###############################################################
#  Generated by:      Cadence Innovus 21.14-s109_1
#  OS:                Linux x86_64(Host ID caen-vnc-mi15.engin.umich.edu)
#  Generated on:      Sun Mar 26 22:47:20 2023
#  Design:            decoder
#  Command:           write_lef_abstract /afs/umich.edu/class/eecs627/w23/students/yihengfu/HW/apr/data/decoder.lef -specifyTopLayer 4 -stripePin -PGpinLayers 4
###############################################################

VERSION 5.8 ;

BUSBITCHARS "[]" ;
DIVIDERCHAR "/" ;

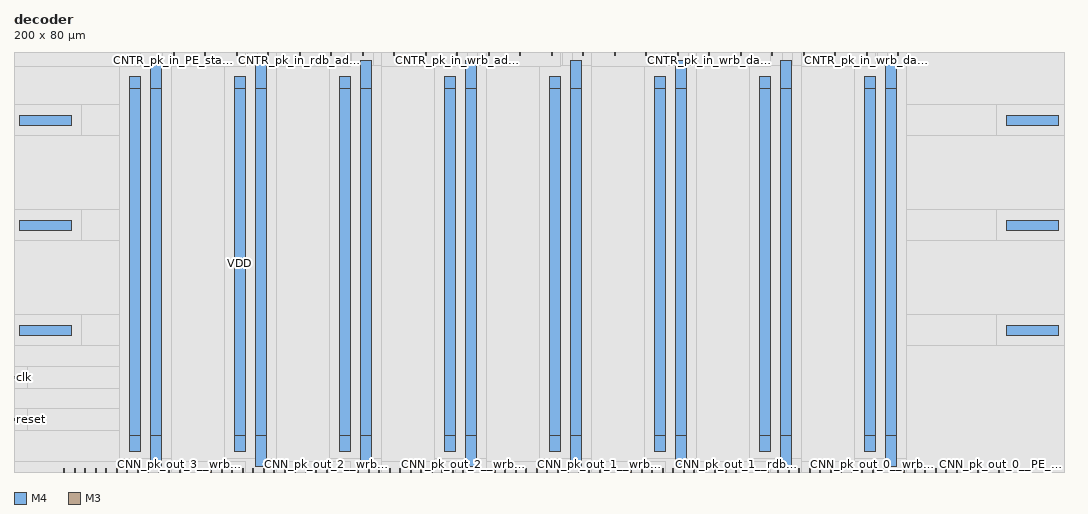
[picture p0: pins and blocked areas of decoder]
MACRO decoder
  CLASS BLOCK ;
  SIZE 200.000000 BY 80.000000 ;
  FOREIGN decoder 0.000000 0.000000 ;
  ORIGIN 0 0 ;
  SYMMETRY X Y R90 ;
  PIN clk
    DIRECTION INPUT ;
    USE SIGNAL ;
    ANTENNAPARTIALMETALAREA 7.72 LAYER M4  ;
    ANTENNAPARTIALMETALSIDEAREA 0.0776 LAYER M4  ;
    ANTENNAMODEL OXIDE1 ;
    ANTENNAGATEAREA 0.2136 LAYER M4  ;
    ANTENNAMAXAREACAR 37.7463 LAYER M4  ;
    ANTENNAMAXSIDEAREACAR 0.384363 LAYER M4  ;
    ANTENNAMAXCUTCAR 0.93633 LAYER V4  ;
    PORT
      LAYER M4 ;
        RECT 0.000000 17.900000 0.600000 18.100000 ;
    END
  END clk
  PIN reset
    DIRECTION INPUT ;
    USE SIGNAL ;
    ANTENNAPARTIALMETALAREA 0.18 LAYER M4  ;
    ANTENNAPARTIALMETALSIDEAREA 0.0022 LAYER M4  ;
    ANTENNAMODEL OXIDE1 ;
    ANTENNAGATEAREA 0.0888 LAYER M4  ;
    ANTENNAMAXAREACAR 64.3829 LAYER M4  ;
    ANTENNAMAXSIDEAREACAR 0.66509 LAYER M4  ;
    ANTENNAMAXCUTCAR 2.25225 LAYER V4  ;
    PORT
      LAYER M4 ;
        RECT 0.000000 9.900000 0.600000 10.100000 ;
    END
  END reset
  PIN CNTR_pk_in_PE_state__2_
    DIRECTION INPUT ;
    USE SIGNAL ;
    ANTENNAPARTIALMETALAREA 0.88 LAYER M3  ;
    ANTENNAPARTIALMETALSIDEAREA 0.0088 LAYER M3  ;
    ANTENNAPARTIALCUTAREA 0.08 LAYER V3  ;
    ANTENNAPARTIALMETALAREA 5.48 LAYER M4  ;
    ANTENNAPARTIALMETALSIDEAREA 0.0552 LAYER M4  ;
    ANTENNAMODEL OXIDE1 ;
    ANTENNAGATEAREA 0.0888 LAYER M4  ;
    ANTENNAMAXAREACAR 95.6892 LAYER M4  ;
    ANTENNAMAXSIDEAREACAR 0.973649 LAYER M4  ;
    ANTENNAMAXCUTCAR 2.25225 LAYER V4  ;
    PORT
      LAYER M3 ;
        RECT 42.300000 79.400000 42.500000 80.000000 ;
    END
  END CNTR_pk_in_PE_state__2_
  PIN CNTR_pk_in_PE_state__1_
    DIRECTION INPUT ;
    USE SIGNAL ;
    ANTENNAPARTIALMETALAREA 0.32 LAYER M3  ;
    ANTENNAPARTIALMETALSIDEAREA 0.0032 LAYER M3  ;
    ANTENNAPARTIALCUTAREA 0.08 LAYER V3  ;
    ANTENNAPARTIALMETALAREA 1.48 LAYER M4  ;
    ANTENNAPARTIALMETALSIDEAREA 0.0152 LAYER M4  ;
    ANTENNAMODEL OXIDE1 ;
    ANTENNAGATEAREA 0.0888 LAYER M4  ;
    ANTENNAMAXAREACAR 68.2117 LAYER M4  ;
    ANTENNAMAXSIDEAREACAR 0.703378 LAYER M4  ;
    ANTENNAMAXCUTCAR 2.25225 LAYER V4  ;
    PORT
      LAYER M3 ;
        RECT 36.300000 79.400000 36.500000 80.000000 ;
    END
  END CNTR_pk_in_PE_state__1_
  PIN CNTR_pk_in_PE_state__0_
    DIRECTION INPUT ;
    USE SIGNAL ;
    ANTENNAPARTIALMETALAREA 0.32 LAYER M3  ;
    ANTENNAPARTIALMETALSIDEAREA 0.0032 LAYER M3  ;
    ANTENNAPARTIALCUTAREA 0.08 LAYER V3  ;
    ANTENNAPARTIALMETALAREA 3.88 LAYER M4  ;
    ANTENNAPARTIALMETALSIDEAREA 0.0392 LAYER M4  ;
    ANTENNAMODEL OXIDE1 ;
    ANTENNAGATEAREA 0.0888 LAYER M4  ;
    ANTENNAMAXAREACAR 63.7072 LAYER M4  ;
    ANTENNAMAXSIDEAREACAR 0.658333 LAYER M4  ;
    ANTENNAMAXCUTCAR 2.25225 LAYER V4  ;
    PORT
      LAYER M3 ;
        RECT 30.300000 79.400000 30.500000 80.000000 ;
    END
  END CNTR_pk_in_PE_state__0_
  PIN CNTR_pk_in_wrb_data__7_
    DIRECTION INPUT ;
    USE SIGNAL ;
    ANTENNAPARTIALMETALAREA 0.16 LAYER M3  ;
    ANTENNAPARTIALMETALSIDEAREA 0.0016 LAYER M3  ;
    ANTENNAPARTIALCUTAREA 0.08 LAYER V3  ;
    ANTENNAPARTIALMETALAREA 4.04 LAYER M4  ;
    ANTENNAPARTIALMETALSIDEAREA 0.0408 LAYER M4  ;
    ANTENNAMODEL OXIDE1 ;
    ANTENNAGATEAREA 0.0888 LAYER M4  ;
    ANTENNAMAXAREACAR 57.8514 LAYER M4  ;
    ANTENNAMAXSIDEAREACAR 0.59527 LAYER M4  ;
    ANTENNAMAXCUTCAR 2.25225 LAYER V4  ;
    PORT
      LAYER M3 ;
        RECT 168.300000 79.400000 168.500000 80.000000 ;
    END
  END CNTR_pk_in_wrb_data__7_
  PIN CNTR_pk_in_wrb_data__6_
    DIRECTION INPUT ;
    USE SIGNAL ;
    ANTENNAPARTIALMETALAREA 1.12 LAYER M3  ;
    ANTENNAPARTIALMETALSIDEAREA 0.0112 LAYER M3  ;
    ANTENNAPARTIALCUTAREA 0.08 LAYER V3  ;
    ANTENNAPARTIALMETALAREA 1.48 LAYER M4  ;
    ANTENNAPARTIALMETALSIDEAREA 0.0152 LAYER M4  ;
    ANTENNAMODEL OXIDE1 ;
    ANTENNAGATEAREA 0.0888 LAYER M4  ;
    ANTENNAMAXAREACAR 49.7432 LAYER M4  ;
    ANTENNAMAXSIDEAREACAR 0.514189 LAYER M4  ;
    ANTENNAMAXCUTCAR 2.25225 LAYER V4  ;
    PORT
      LAYER M3 ;
        RECT 162.300000 79.400000 162.500000 80.000000 ;
    END
  END CNTR_pk_in_wrb_data__6_
  PIN CNTR_pk_in_wrb_data__5_
    DIRECTION INPUT ;
    USE SIGNAL ;
    ANTENNAPARTIALMETALAREA 1.2 LAYER M3  ;
    ANTENNAPARTIALMETALSIDEAREA 0.012 LAYER M3  ;
    ANTENNAPARTIALCUTAREA 0.08 LAYER V3  ;
    ANTENNAPARTIALMETALAREA 3.96 LAYER M4  ;
    ANTENNAPARTIALMETALSIDEAREA 0.04 LAYER M4  ;
    ANTENNAMODEL OXIDE1 ;
    ANTENNAGATEAREA 0.0888 LAYER M4  ;
    ANTENNAMAXAREACAR 61.455 LAYER M4  ;
    ANTENNAMAXSIDEAREACAR 0.631306 LAYER M4  ;
    ANTENNAMAXCUTCAR 2.25225 LAYER V4  ;
    PORT
      LAYER M3 ;
        RECT 156.300000 79.400000 156.500000 80.000000 ;
    END
  END CNTR_pk_in_wrb_data__5_
  PIN CNTR_pk_in_wrb_data__4_
    DIRECTION INPUT ;
    USE SIGNAL ;
    ANTENNAPARTIALMETALAREA 0.4 LAYER M3  ;
    ANTENNAPARTIALMETALSIDEAREA 0.004 LAYER M3  ;
    ANTENNAPARTIALCUTAREA 0.08 LAYER V3  ;
    ANTENNAPARTIALMETALAREA 1.56 LAYER M4  ;
    ANTENNAPARTIALMETALSIDEAREA 0.016 LAYER M4  ;
    ANTENNAMODEL OXIDE1 ;
    ANTENNAGATEAREA 0.0888 LAYER M4  ;
    ANTENNAMAXAREACAR 33.527 LAYER M4  ;
    ANTENNAMAXSIDEAREACAR 0.352027 LAYER M4  ;
    ANTENNAMAXCUTCAR 2.25225 LAYER V4  ;
    PORT
      LAYER M3 ;
        RECT 150.300000 79.400000 150.500000 80.000000 ;
    END
  END CNTR_pk_in_wrb_data__4_
  PIN CNTR_pk_in_wrb_data__3_
    DIRECTION INPUT ;
    USE SIGNAL ;
    ANTENNAPARTIALMETALAREA 0.24 LAYER M3  ;
    ANTENNAPARTIALMETALSIDEAREA 0.0024 LAYER M3  ;
    ANTENNAPARTIALCUTAREA 0.08 LAYER V3  ;
    ANTENNAPARTIALMETALAREA 1.64 LAYER M4  ;
    ANTENNAPARTIALMETALSIDEAREA 0.0168 LAYER M4  ;
    ANTENNAMODEL OXIDE1 ;
    ANTENNAGATEAREA 0.0888 LAYER M4  ;
    ANTENNAMAXAREACAR 27.2207 LAYER M4  ;
    ANTENNAMAXSIDEAREACAR 0.288964 LAYER M4  ;
    ANTENNAMAXCUTCAR 2.25225 LAYER V4  ;
    PORT
      LAYER M3 ;
        RECT 144.300000 79.400000 144.500000 80.000000 ;
    END
  END CNTR_pk_in_wrb_data__3_
  PIN CNTR_pk_in_wrb_data__2_
    DIRECTION INPUT ;
    USE SIGNAL ;
    ANTENNAPARTIALMETALAREA 1.2 LAYER M3  ;
    ANTENNAPARTIALMETALSIDEAREA 0.012 LAYER M3  ;
    ANTENNAPARTIALCUTAREA 0.08 LAYER V3  ;
    ANTENNAPARTIALMETALAREA 1.48 LAYER M4  ;
    ANTENNAPARTIALMETALSIDEAREA 0.0152 LAYER M4  ;
    ANTENNAMODEL OXIDE1 ;
    ANTENNAGATEAREA 0.0888 LAYER M4  ;
    ANTENNAMAXAREACAR 37.5811 LAYER M4  ;
    ANTENNAMAXSIDEAREACAR 0.397072 LAYER M4  ;
    ANTENNAMAXCUTCAR 2.25225 LAYER V4  ;
    PORT
      LAYER M3 ;
        RECT 138.300000 79.400000 138.500000 80.000000 ;
    END
  END CNTR_pk_in_wrb_data__2_
  PIN CNTR_pk_in_wrb_data__1_
    DIRECTION INPUT ;
    USE SIGNAL ;
    ANTENNAPARTIALMETALAREA 0.32 LAYER M3  ;
    ANTENNAPARTIALMETALSIDEAREA 0.0032 LAYER M3  ;
    ANTENNAPARTIALCUTAREA 0.08 LAYER V3  ;
    ANTENNAPARTIALMETALAREA 6.92 LAYER M4  ;
    ANTENNAPARTIALMETALSIDEAREA 0.0696 LAYER M4  ;
    ANTENNAMODEL OXIDE1 ;
    ANTENNAGATEAREA 0.0888 LAYER M4  ;
    ANTENNAMAXAREACAR 87.5811 LAYER M4  ;
    ANTENNAMAXSIDEAREACAR 0.892568 LAYER M4  ;
    ANTENNAMAXCUTCAR 2.25225 LAYER V4  ;
    PORT
      LAYER M3 ;
        RECT 132.300000 79.400000 132.500000 80.000000 ;
    END
  END CNTR_pk_in_wrb_data__1_
  PIN CNTR_pk_in_wrb_data__0_
    DIRECTION INPUT ;
    USE SIGNAL ;
    ANTENNAPARTIALMETALAREA 1.12 LAYER M3  ;
    ANTENNAPARTIALMETALSIDEAREA 0.0112 LAYER M3  ;
    ANTENNAPARTIALCUTAREA 0.08 LAYER V3  ;
    ANTENNAPARTIALMETALAREA 1.48 LAYER M4  ;
    ANTENNAPARTIALMETALSIDEAREA 0.0152 LAYER M4  ;
    ANTENNAMODEL OXIDE1 ;
    ANTENNAGATEAREA 0.0888 LAYER M4  ;
    ANTENNAMAXAREACAR 31.2748 LAYER M4  ;
    ANTENNAMAXSIDEAREACAR 0.334009 LAYER M4  ;
    ANTENNAMAXCUTCAR 2.25225 LAYER V4  ;
    PORT
      LAYER M3 ;
        RECT 126.300000 79.400000 126.500000 80.000000 ;
    END
  END CNTR_pk_in_wrb_data__0_
  PIN CNTR_pk_in_wrb_addr__7_
    DIRECTION INPUT ;
    USE SIGNAL ;
    ANTENNAPARTIALMETALAREA 0.4 LAYER M3  ;
    ANTENNAPARTIALMETALSIDEAREA 0.004 LAYER M3  ;
    ANTENNAPARTIALCUTAREA 0.08 LAYER V3  ;
    ANTENNAPARTIALMETALAREA 1.64 LAYER M4  ;
    ANTENNAPARTIALMETALSIDEAREA 0.0168 LAYER M4  ;
    ANTENNAMODEL OXIDE1 ;
    ANTENNAGATEAREA 0.0888 LAYER M4  ;
    ANTENNAMAXAREACAR 43.4369 LAYER M4  ;
    ANTENNAMAXSIDEAREACAR 0.451126 LAYER M4  ;
    ANTENNAMAXCUTCAR 2.25225 LAYER V4  ;
    PORT
      LAYER M3 ;
        RECT 120.300000 79.400000 120.500000 80.000000 ;
    END
  END CNTR_pk_in_wrb_addr__7_
  PIN CNTR_pk_in_wrb_addr__6_
    DIRECTION INPUT ;
    USE SIGNAL ;
    ANTENNAPARTIALMETALAREA 0.96 LAYER M3  ;
    ANTENNAPARTIALMETALSIDEAREA 0.0096 LAYER M3  ;
    ANTENNAPARTIALCUTAREA 0.08 LAYER V3  ;
    ANTENNAPARTIALMETALAREA 2.28 LAYER M4  ;
    ANTENNAPARTIALMETALSIDEAREA 0.0232 LAYER M4  ;
    ANTENNAMODEL OXIDE1 ;
    ANTENNAGATEAREA 0.0888 LAYER M4  ;
    ANTENNAMAXAREACAR 38.482 LAYER M4  ;
    ANTENNAMAXSIDEAREACAR 0.406081 LAYER M4  ;
    ANTENNAMAXCUTCAR 2.25225 LAYER V4  ;
    PORT
      LAYER M3 ;
        RECT 114.300000 79.400000 114.500000 80.000000 ;
    END
  END CNTR_pk_in_wrb_addr__6_
  PIN CNTR_pk_in_wrb_addr__5_
    DIRECTION INPUT ;
    USE SIGNAL ;
    ANTENNAPARTIALMETALAREA 0.16 LAYER M3  ;
    ANTENNAPARTIALMETALSIDEAREA 0.0016 LAYER M3  ;
    ANTENNAPARTIALCUTAREA 0.08 LAYER V3  ;
    ANTENNAPARTIALMETALAREA 7.96 LAYER M4  ;
    ANTENNAPARTIALMETALSIDEAREA 0.08 LAYER M4  ;
    ANTENNAMODEL OXIDE1 ;
    ANTENNAGATEAREA 0.0888 LAYER M4  ;
    ANTENNAMAXAREACAR 101.095 LAYER M4  ;
    ANTENNAMAXSIDEAREACAR 1.0277 LAYER M4  ;
    ANTENNAMAXCUTCAR 2.25225 LAYER V4  ;
    PORT
      LAYER M3 ;
        RECT 108.300000 79.400000 108.500000 80.000000 ;
    END
  END CNTR_pk_in_wrb_addr__5_
  PIN CNTR_pk_in_wrb_addr__4_
    DIRECTION INPUT ;
    USE SIGNAL ;
    ANTENNAPARTIALMETALAREA 0.8 LAYER M3  ;
    ANTENNAPARTIALMETALSIDEAREA 0.008 LAYER M3  ;
    ANTENNAPARTIALCUTAREA 0.08 LAYER V3  ;
    ANTENNAPARTIALMETALAREA 1.32 LAYER M4  ;
    ANTENNAPARTIALMETALSIDEAREA 0.0136 LAYER M4  ;
    ANTENNAMODEL OXIDE1 ;
    ANTENNAGATEAREA 0.0888 LAYER M4  ;
    ANTENNAMAXAREACAR 25.8694 LAYER M4  ;
    ANTENNAMAXSIDEAREACAR 0.279955 LAYER M4  ;
    ANTENNAMAXCUTCAR 2.25225 LAYER V4  ;
    PORT
      LAYER M3 ;
        RECT 102.300000 79.400000 102.500000 80.000000 ;
    END
  END CNTR_pk_in_wrb_addr__4_
  PIN CNTR_pk_in_wrb_addr__3_
    DIRECTION INPUT ;
    USE SIGNAL ;
    ANTENNAPARTIALMETALAREA 1.12 LAYER M3  ;
    ANTENNAPARTIALMETALSIDEAREA 0.0112 LAYER M3  ;
    ANTENNAPARTIALCUTAREA 0.08 LAYER V3  ;
    ANTENNAPARTIALMETALAREA 1.48 LAYER M4  ;
    ANTENNAPARTIALMETALSIDEAREA 0.0152 LAYER M4  ;
    ANTENNAMODEL OXIDE1 ;
    ANTENNAGATEAREA 0.0888 LAYER M4  ;
    ANTENNAMAXAREACAR 26.7703 LAYER M4  ;
    ANTENNAMAXSIDEAREACAR 0.288964 LAYER M4  ;
    ANTENNAMAXCUTCAR 2.25225 LAYER V4  ;
    PORT
      LAYER M3 ;
        RECT 96.300000 79.400000 96.500000 80.000000 ;
    END
  END CNTR_pk_in_wrb_addr__3_
  PIN CNTR_pk_in_wrb_addr__2_
    DIRECTION INPUT ;
    USE SIGNAL ;
    ANTENNAPARTIALMETALAREA 1.2 LAYER M3  ;
    ANTENNAPARTIALMETALSIDEAREA 0.012 LAYER M3  ;
    ANTENNAPARTIALCUTAREA 0.08 LAYER V3  ;
    ANTENNAPARTIALMETALAREA 4.68 LAYER M4  ;
    ANTENNAPARTIALMETALSIDEAREA 0.0472 LAYER M4  ;
    ANTENNAMODEL OXIDE1 ;
    ANTENNAGATEAREA 0.0888 LAYER M4  ;
    ANTENNAMAXAREACAR 65.509 LAYER M4  ;
    ANTENNAMAXSIDEAREACAR 0.676351 LAYER M4  ;
    ANTENNAMAXCUTCAR 2.25225 LAYER V4  ;
    PORT
      LAYER M3 ;
        RECT 90.300000 79.400000 90.500000 80.000000 ;
    END
  END CNTR_pk_in_wrb_addr__2_
  PIN CNTR_pk_in_wrb_addr__1_
    DIRECTION INPUT ;
    USE SIGNAL ;
    ANTENNAPARTIALMETALAREA 0.64 LAYER M3  ;
    ANTENNAPARTIALMETALSIDEAREA 0.0064 LAYER M3  ;
    ANTENNAPARTIALCUTAREA 0.08 LAYER V3  ;
    ANTENNAPARTIALMETALAREA 2.04 LAYER M4  ;
    ANTENNAPARTIALMETALSIDEAREA 0.0208 LAYER M4  ;
    ANTENNAMODEL OXIDE1 ;
    ANTENNAGATEAREA 0.0888 LAYER M4  ;
    ANTENNAMAXAREACAR 33.9775 LAYER M4  ;
    ANTENNAMAXSIDEAREACAR 0.361036 LAYER M4  ;
    ANTENNAMAXCUTCAR 2.25225 LAYER V4  ;
    PORT
      LAYER M3 ;
        RECT 84.300000 79.400000 84.500000 80.000000 ;
    END
  END CNTR_pk_in_wrb_addr__1_
  PIN CNTR_pk_in_wrb_addr__0_
    DIRECTION INPUT ;
    USE SIGNAL ;
    ANTENNAPARTIALMETALAREA 0.16 LAYER M3  ;
    ANTENNAPARTIALMETALSIDEAREA 0.0016 LAYER M3  ;
    ANTENNAPARTIALCUTAREA 0.08 LAYER V3  ;
    ANTENNAPARTIALMETALAREA 1.56 LAYER M4  ;
    ANTENNAPARTIALMETALSIDEAREA 0.016 LAYER M4  ;
    ANTENNAMODEL OXIDE1 ;
    ANTENNAGATEAREA 0.0888 LAYER M4  ;
    ANTENNAMAXAREACAR 38.482 LAYER M4  ;
    ANTENNAMAXSIDEAREACAR 0.406081 LAYER M4  ;
    ANTENNAMAXCUTCAR 2.25225 LAYER V4  ;
    PORT
      LAYER M3 ;
        RECT 78.300000 79.400000 78.500000 80.000000 ;
    END
  END CNTR_pk_in_wrb_addr__0_
  PIN CNTR_pk_in_wrb_
    DIRECTION INPUT ;
    USE SIGNAL ;
    ANTENNAPARTIALMETALAREA 1.2 LAYER M3  ;
    ANTENNAPARTIALMETALSIDEAREA 0.012 LAYER M3  ;
    ANTENNAPARTIALCUTAREA 0.08 LAYER V3  ;
    ANTENNAPARTIALMETALAREA 1.64 LAYER M4  ;
    ANTENNAPARTIALMETALSIDEAREA 0.0168 LAYER M4  ;
    ANTENNAMODEL OXIDE1 ;
    ANTENNAGATEAREA 0.0888 LAYER M4  ;
    ANTENNAMAXAREACAR 27.6712 LAYER M4  ;
    ANTENNAMAXSIDEAREACAR 0.297973 LAYER M4  ;
    ANTENNAMAXCUTCAR 2.25225 LAYER V4  ;
    PORT
      LAYER M3 ;
        RECT 72.300000 79.400000 72.500000 80.000000 ;
    END
  END CNTR_pk_in_wrb_
  PIN CNTR_pk_in_rdb_addr__3_
    DIRECTION INPUT ;
    USE SIGNAL ;
    ANTENNAPARTIALMETALAREA 0.48 LAYER M3  ;
    ANTENNAPARTIALMETALSIDEAREA 0.0048 LAYER M3  ;
    ANTENNAPARTIALCUTAREA 0.08 LAYER V3  ;
    ANTENNAPARTIALMETALAREA 6.28 LAYER M4  ;
    ANTENNAPARTIALMETALSIDEAREA 0.0632 LAYER M4  ;
    ANTENNAMODEL OXIDE1 ;
    ANTENNAGATEAREA 0.0888 LAYER M4  ;
    ANTENNAMAXAREACAR 80.3739 LAYER M4  ;
    ANTENNAMAXSIDEAREACAR 0.820495 LAYER M4  ;
    ANTENNAMAXCUTCAR 2.25225 LAYER V4  ;
    PORT
      LAYER M3 ;
        RECT 66.300000 79.400000 66.500000 80.000000 ;
    END
  END CNTR_pk_in_rdb_addr__3_
  PIN CNTR_pk_in_rdb_addr__2_
    DIRECTION INPUT ;
    USE SIGNAL ;
    ANTENNAPARTIALMETALAREA 0.72 LAYER M3  ;
    ANTENNAPARTIALMETALSIDEAREA 0.0072 LAYER M3  ;
    ANTENNAPARTIALCUTAREA 0.08 LAYER V3  ;
    ANTENNAPARTIALMETALAREA 1.48 LAYER M4  ;
    ANTENNAPARTIALMETALSIDEAREA 0.0152 LAYER M4  ;
    ANTENNAMODEL OXIDE1 ;
    ANTENNAGATEAREA 0.0888 LAYER M4  ;
    ANTENNAMAXAREACAR 26.7703 LAYER M4  ;
    ANTENNAMAXSIDEAREACAR 0.288964 LAYER M4  ;
    ANTENNAMAXCUTCAR 2.25225 LAYER V4  ;
    PORT
      LAYER M3 ;
        RECT 60.300000 79.400000 60.500000 80.000000 ;
    END
  END CNTR_pk_in_rdb_addr__2_
  PIN CNTR_pk_in_rdb_addr__1_
    DIRECTION INPUT ;
    USE SIGNAL ;
    ANTENNAPARTIALMETALAREA 1.12 LAYER M3  ;
    ANTENNAPARTIALMETALSIDEAREA 0.0112 LAYER M3  ;
    ANTENNAPARTIALCUTAREA 0.08 LAYER V3  ;
    ANTENNAPARTIALMETALAREA 5.4 LAYER M4  ;
    ANTENNAPARTIALMETALSIDEAREA 0.0544 LAYER M4  ;
    ANTENNAMODEL OXIDE1 ;
    ANTENNAGATEAREA 0.0888 LAYER M4  ;
    ANTENNAMAXAREACAR 82.1757 LAYER M4  ;
    ANTENNAMAXSIDEAREACAR 0.838513 LAYER M4  ;
    ANTENNAMAXCUTCAR 2.25225 LAYER V4  ;
    PORT
      LAYER M3 ;
        RECT 54.300000 79.400000 54.500000 80.000000 ;
    END
  END CNTR_pk_in_rdb_addr__1_
  PIN CNTR_pk_in_rdb_addr__0_
    DIRECTION INPUT ;
    USE SIGNAL ;
    ANTENNAPARTIALMETALAREA 0.14 LAYER M3  ;
    ANTENNAPARTIALMETALSIDEAREA 0.0014 LAYER M3  ;
    ANTENNAPARTIALCUTAREA 0.08 LAYER V3  ;
    ANTENNAPARTIALMETALAREA 1.4 LAYER M4  ;
    ANTENNAPARTIALMETALSIDEAREA 0.0144 LAYER M4  ;
    ANTENNAMODEL OXIDE1 ;
    ANTENNAGATEAREA 0.0888 LAYER M4  ;
    ANTENNAMAXAREACAR 44.3378 LAYER M4  ;
    ANTENNAMAXSIDEAREACAR 0.460135 LAYER M4  ;
    ANTENNAMAXCUTCAR 2.25225 LAYER V4  ;
    PORT
      LAYER M3 ;
        RECT 48.300000 79.400000 48.500000 80.000000 ;
    END
  END CNTR_pk_in_rdb_addr__0_
  PIN CNN_pk_out_3__PE_state__2_
    DIRECTION OUTPUT ;
    USE SIGNAL ;
    ANTENNAPARTIALMETALAREA 0.16 LAYER M3  ;
    ANTENNAPARTIALMETALSIDEAREA 0.0016 LAYER M3  ;
    ANTENNAPARTIALCUTAREA 0.08 LAYER V3  ;
    ANTENNADIFFAREA 3.52 LAYER M4  ;
    ANTENNAPARTIALMETALAREA 30.28 LAYER M4  ;
    ANTENNAPARTIALMETALSIDEAREA 0.3048 LAYER M4  ;
    PORT
      LAYER M3 ;
        RECT 49.500000 0.000000 49.700000 0.600000 ;
    END
  END CNN_pk_out_3__PE_state__2_
  PIN CNN_pk_out_3__PE_state__1_
    DIRECTION OUTPUT ;
    USE SIGNAL ;
    ANTENNAPARTIALMETALAREA 0.16 LAYER M3  ;
    ANTENNAPARTIALMETALSIDEAREA 0.0016 LAYER M3  ;
    ANTENNAPARTIALCUTAREA 0.08 LAYER V3  ;
    ANTENNADIFFAREA 3.52 LAYER M4  ;
    ANTENNAPARTIALMETALAREA 8.88 LAYER M4  ;
    ANTENNAPARTIALMETALSIDEAREA 0.0904 LAYER M4  ;
    PORT
      LAYER M3 ;
        RECT 51.500000 0.000000 51.700000 0.600000 ;
    END
  END CNN_pk_out_3__PE_state__1_
  PIN CNN_pk_out_3__PE_state__0_
    DIRECTION OUTPUT ;
    USE SIGNAL ;
    ANTENNAPARTIALMETALAREA 0.16 LAYER M3  ;
    ANTENNAPARTIALMETALSIDEAREA 0.0016 LAYER M3  ;
    ANTENNAPARTIALCUTAREA 0.08 LAYER V3  ;
    ANTENNADIFFAREA 3.52 LAYER M4  ;
    ANTENNAPARTIALMETALAREA 7.96 LAYER M4  ;
    ANTENNAPARTIALMETALSIDEAREA 0.0816 LAYER M4  ;
    PORT
      LAYER M3 ;
        RECT 53.500000 0.000000 53.700000 0.600000 ;
    END
  END CNN_pk_out_3__PE_state__0_
  PIN CNN_pk_out_3__wrb_data__7_
    DIRECTION OUTPUT ;
    USE SIGNAL ;
    ANTENNAPARTIALMETALAREA 0.16 LAYER M3  ;
    ANTENNAPARTIALMETALSIDEAREA 0.0016 LAYER M3  ;
    ANTENNAPARTIALCUTAREA 0.08 LAYER V3  ;
    ANTENNADIFFAREA 3.52 LAYER M4  ;
    ANTENNAPARTIALMETALAREA 8.24 LAYER M4  ;
    ANTENNAPARTIALMETALSIDEAREA 0.084 LAYER M4  ;
    PORT
      LAYER M3 ;
        RECT 9.500000 0.000000 9.700000 0.600000 ;
    END
  END CNN_pk_out_3__wrb_data__7_
  PIN CNN_pk_out_3__wrb_data__6_
    DIRECTION OUTPUT ;
    USE SIGNAL ;
    ANTENNAPARTIALMETALAREA 0.32 LAYER M3  ;
    ANTENNAPARTIALMETALSIDEAREA 0.0032 LAYER M3  ;
    ANTENNAPARTIALCUTAREA 0.08 LAYER V3  ;
    ANTENNADIFFAREA 3.52 LAYER M4  ;
    ANTENNAPARTIALMETALAREA 9.12 LAYER M4  ;
    ANTENNAPARTIALMETALSIDEAREA 0.0928 LAYER M4  ;
    PORT
      LAYER M3 ;
        RECT 11.500000 0.000000 11.700000 0.600000 ;
    END
  END CNN_pk_out_3__wrb_data__6_
  PIN CNN_pk_out_3__wrb_data__5_
    DIRECTION OUTPUT ;
    USE SIGNAL ;
    ANTENNAPARTIALMETALAREA 0.4 LAYER M3  ;
    ANTENNAPARTIALMETALSIDEAREA 0.004 LAYER M3  ;
    ANTENNAPARTIALCUTAREA 0.08 LAYER V3  ;
    ANTENNADIFFAREA 3.52 LAYER M4  ;
    ANTENNAPARTIALMETALAREA 26.16 LAYER M4  ;
    ANTENNAPARTIALMETALSIDEAREA 0.2632 LAYER M4  ;
    PORT
      LAYER M3 ;
        RECT 13.500000 0.000000 13.700000 0.600000 ;
    END
  END CNN_pk_out_3__wrb_data__5_
  PIN CNN_pk_out_3__wrb_data__4_
    DIRECTION OUTPUT ;
    USE SIGNAL ;
    ANTENNAPARTIALMETALAREA 0.4 LAYER M3  ;
    ANTENNAPARTIALMETALSIDEAREA 0.004 LAYER M3  ;
    ANTENNAPARTIALCUTAREA 0.08 LAYER V3  ;
    ANTENNADIFFAREA 3.52 LAYER M4  ;
    ANTENNAPARTIALMETALAREA 4.16 LAYER M4  ;
    ANTENNAPARTIALMETALSIDEAREA 0.0432 LAYER M4  ;
    PORT
      LAYER M3 ;
        RECT 15.500000 0.000000 15.700000 0.600000 ;
    END
  END CNN_pk_out_3__wrb_data__4_
  PIN CNN_pk_out_3__wrb_data__3_
    DIRECTION OUTPUT ;
    USE SIGNAL ;
    ANTENNAPARTIALMETALAREA 0.08 LAYER M3  ;
    ANTENNAPARTIALMETALSIDEAREA 0.0008 LAYER M3  ;
    ANTENNAPARTIALCUTAREA 0.04 LAYER V3  ;
    ANTENNADIFFAREA 3.52 LAYER M4  ;
    ANTENNAPARTIALMETALAREA 23.12 LAYER M4  ;
    ANTENNAPARTIALMETALSIDEAREA 0.2328 LAYER M4  ;
    PORT
      LAYER M3 ;
        RECT 17.500000 0.000000 17.700000 0.600000 ;
    END
  END CNN_pk_out_3__wrb_data__3_
  PIN CNN_pk_out_3__wrb_data__2_
    DIRECTION OUTPUT ;
    USE SIGNAL ;
    ANTENNAPARTIALMETALAREA 0.16 LAYER M3  ;
    ANTENNAPARTIALMETALSIDEAREA 0.0016 LAYER M3  ;
    ANTENNAPARTIALCUTAREA 0.08 LAYER V3  ;
    ANTENNADIFFAREA 3.52 LAYER M4  ;
    ANTENNAPARTIALMETALAREA 15.2 LAYER M4  ;
    ANTENNAPARTIALMETALSIDEAREA 0.1536 LAYER M4  ;
    PORT
      LAYER M3 ;
        RECT 19.500000 0.000000 19.700000 0.600000 ;
    END
  END CNN_pk_out_3__wrb_data__2_
  PIN CNN_pk_out_3__wrb_data__1_
    DIRECTION OUTPUT ;
    USE SIGNAL ;
    ANTENNAPARTIALMETALAREA 0.16 LAYER M3  ;
    ANTENNAPARTIALMETALSIDEAREA 0.0016 LAYER M3  ;
    ANTENNAPARTIALCUTAREA 0.08 LAYER V3  ;
    ANTENNADIFFAREA 3.52 LAYER M4  ;
    ANTENNAPARTIALMETALAREA 23.6 LAYER M4  ;
    ANTENNAPARTIALMETALSIDEAREA 0.2376 LAYER M4  ;
    PORT
      LAYER M3 ;
        RECT 21.500000 0.000000 21.700000 0.600000 ;
    END
  END CNN_pk_out_3__wrb_data__1_
  PIN CNN_pk_out_3__wrb_data__0_
    DIRECTION OUTPUT ;
    USE SIGNAL ;
    ANTENNAPARTIALMETALAREA 0.4 LAYER M3  ;
    ANTENNAPARTIALMETALSIDEAREA 0.004 LAYER M3  ;
    ANTENNAPARTIALCUTAREA 0.08 LAYER V3  ;
    ANTENNADIFFAREA 3.52 LAYER M4  ;
    ANTENNAPARTIALMETALAREA 20.84 LAYER M4  ;
    ANTENNAPARTIALMETALSIDEAREA 0.2112 LAYER M4  ;
    PORT
      LAYER M3 ;
        RECT 23.500000 0.000000 23.700000 0.600000 ;
    END
  END CNN_pk_out_3__wrb_data__0_
  PIN CNN_pk_out_3__wrb_addr__3_
    DIRECTION OUTPUT ;
    USE SIGNAL ;
    ANTENNAPARTIALMETALAREA 0.46 LAYER M3  ;
    ANTENNAPARTIALMETALSIDEAREA 0.0046 LAYER M3  ;
    ANTENNAPARTIALCUTAREA 0.08 LAYER V3  ;
    ANTENNADIFFAREA 3.52 LAYER M4  ;
    ANTENNAPARTIALMETALAREA 22.16 LAYER M4  ;
    ANTENNAPARTIALMETALSIDEAREA 0.2232 LAYER M4  ;
    PORT
      LAYER M3 ;
        RECT 25.500000 0.000000 25.700000 0.600000 ;
    END
  END CNN_pk_out_3__wrb_addr__3_
  PIN CNN_pk_out_3__wrb_addr__2_
    DIRECTION OUTPUT ;
    USE SIGNAL ;
    ANTENNAPARTIALMETALAREA 0.24 LAYER M3  ;
    ANTENNAPARTIALMETALSIDEAREA 0.0024 LAYER M3  ;
    ANTENNAPARTIALCUTAREA 0.08 LAYER V3  ;
    ANTENNADIFFAREA 3.52 LAYER M4  ;
    ANTENNAPARTIALMETALAREA 27.92 LAYER M4  ;
    ANTENNAPARTIALMETALSIDEAREA 0.2808 LAYER M4  ;
    PORT
      LAYER M3 ;
        RECT 27.500000 0.000000 27.700000 0.600000 ;
    END
  END CNN_pk_out_3__wrb_addr__2_
  PIN CNN_pk_out_3__wrb_addr__1_
    DIRECTION OUTPUT ;
    USE SIGNAL ;
    ANTENNAPARTIALMETALAREA 0.16 LAYER M3  ;
    ANTENNAPARTIALMETALSIDEAREA 0.0016 LAYER M3  ;
    ANTENNAPARTIALCUTAREA 0.08 LAYER V3  ;
    ANTENNADIFFAREA 3.52 LAYER M4  ;
    ANTENNAPARTIALMETALAREA 24.8 LAYER M4  ;
    ANTENNAPARTIALMETALSIDEAREA 0.2496 LAYER M4  ;
    PORT
      LAYER M3 ;
        RECT 29.500000 0.000000 29.700000 0.600000 ;
    END
  END CNN_pk_out_3__wrb_addr__1_
  PIN CNN_pk_out_3__wrb_addr__0_
    DIRECTION OUTPUT ;
    USE SIGNAL ;
    ANTENNAPARTIALMETALAREA 0.16 LAYER M3  ;
    ANTENNAPARTIALMETALSIDEAREA 0.0016 LAYER M3  ;
    ANTENNAPARTIALCUTAREA 0.08 LAYER V3  ;
    ANTENNADIFFAREA 3.52 LAYER M4  ;
    ANTENNAPARTIALMETALAREA 11.96 LAYER M4  ;
    ANTENNAPARTIALMETALSIDEAREA 0.1216 LAYER M4  ;
    PORT
      LAYER M3 ;
        RECT 31.500000 0.000000 31.700000 0.600000 ;
    END
  END CNN_pk_out_3__wrb_addr__0_
  PIN CNN_pk_out_3__wrb__3_
    DIRECTION OUTPUT ;
    USE SIGNAL ;
    ANTENNAPARTIALMETALAREA 0.16 LAYER M3  ;
    ANTENNAPARTIALMETALSIDEAREA 0.0016 LAYER M3  ;
    ANTENNAPARTIALCUTAREA 0.08 LAYER V3  ;
    ANTENNADIFFAREA 2.172 LAYER M4  ;
    ANTENNAPARTIALMETALAREA 2.76 LAYER M4  ;
    ANTENNAPARTIALMETALSIDEAREA 0.028 LAYER M4  ;
    PORT
      LAYER M3 ;
        RECT 33.500000 0.000000 33.700000 0.600000 ;
    END
  END CNN_pk_out_3__wrb__3_
  PIN CNN_pk_out_3__wrb__2_
    DIRECTION OUTPUT ;
    USE SIGNAL ;
    ANTENNAPARTIALMETALAREA 0.32 LAYER M3  ;
    ANTENNAPARTIALMETALSIDEAREA 0.0032 LAYER M3  ;
    ANTENNAPARTIALCUTAREA 0.08 LAYER V3  ;
    ANTENNADIFFAREA 2.172 LAYER M4  ;
    ANTENNAPARTIALMETALAREA 1.96 LAYER M4  ;
    ANTENNAPARTIALMETALSIDEAREA 0.02 LAYER M4  ;
    PORT
      LAYER M3 ;
        RECT 35.500000 0.000000 35.700000 0.600000 ;
    END
  END CNN_pk_out_3__wrb__2_
  PIN CNN_pk_out_3__wrb__1_
    DIRECTION OUTPUT ;
    USE SIGNAL ;
    ANTENNAPARTIALMETALAREA 0.4 LAYER M3  ;
    ANTENNAPARTIALMETALSIDEAREA 0.004 LAYER M3  ;
    ANTENNAPARTIALCUTAREA 0.08 LAYER V3  ;
    ANTENNADIFFAREA 3.196 LAYER M4  ;
    ANTENNAPARTIALMETALAREA 3.88 LAYER M4  ;
    ANTENNAPARTIALMETALSIDEAREA 0.0392 LAYER M4  ;
    PORT
      LAYER M3 ;
        RECT 37.500000 0.000000 37.700000 0.600000 ;
    END
  END CNN_pk_out_3__wrb__1_
  PIN CNN_pk_out_3__wrb__0_
    DIRECTION OUTPUT ;
    USE SIGNAL ;
    ANTENNAPARTIALMETALAREA 0.24 LAYER M3  ;
    ANTENNAPARTIALMETALSIDEAREA 0.0024 LAYER M3  ;
    ANTENNAPARTIALCUTAREA 0.08 LAYER V3  ;
    ANTENNADIFFAREA 3.196 LAYER M4  ;
    ANTENNAPARTIALMETALAREA 3.16 LAYER M4  ;
    ANTENNAPARTIALMETALSIDEAREA 0.032 LAYER M4  ;
    PORT
      LAYER M3 ;
        RECT 39.500000 0.000000 39.700000 0.600000 ;
    END
  END CNN_pk_out_3__wrb__0_
  PIN CNN_pk_out_3__rdb_addr__3_
    DIRECTION OUTPUT ;
    USE SIGNAL ;
    ANTENNAPARTIALMETALAREA 0.4 LAYER M3  ;
    ANTENNAPARTIALMETALSIDEAREA 0.004 LAYER M3  ;
    ANTENNAPARTIALCUTAREA 0.08 LAYER V3  ;
    ANTENNADIFFAREA 3.52 LAYER M4  ;
    ANTENNAPARTIALMETALAREA 16 LAYER M4  ;
    ANTENNAPARTIALMETALSIDEAREA 0.1624 LAYER M4  ;
    PORT
      LAYER M3 ;
        RECT 41.500000 0.000000 41.700000 0.600000 ;
    END
  END CNN_pk_out_3__rdb_addr__3_
  PIN CNN_pk_out_3__rdb_addr__2_
    DIRECTION OUTPUT ;
    USE SIGNAL ;
    ANTENNAPARTIALMETALAREA 0.24 LAYER M3  ;
    ANTENNAPARTIALMETALSIDEAREA 0.0024 LAYER M3  ;
    ANTENNAPARTIALCUTAREA 0.08 LAYER V3  ;
    ANTENNADIFFAREA 3.52 LAYER M4  ;
    ANTENNAPARTIALMETALAREA 10 LAYER M4  ;
    ANTENNAPARTIALMETALSIDEAREA 0.1016 LAYER M4  ;
    PORT
      LAYER M3 ;
        RECT 43.500000 0.000000 43.700000 0.600000 ;
    END
  END CNN_pk_out_3__rdb_addr__2_
  PIN CNN_pk_out_3__rdb_addr__1_
    DIRECTION OUTPUT ;
    USE SIGNAL ;
    ANTENNAPARTIALMETALAREA 0.14 LAYER M3  ;
    ANTENNAPARTIALMETALSIDEAREA 0.0014 LAYER M3  ;
    ANTENNAPARTIALCUTAREA 0.08 LAYER V3  ;
    ANTENNADIFFAREA 3.52 LAYER M4  ;
    ANTENNAPARTIALMETALAREA 6.08 LAYER M4  ;
    ANTENNAPARTIALMETALSIDEAREA 0.0624 LAYER M4  ;
    PORT
      LAYER M3 ;
        RECT 45.500000 0.000000 45.700000 0.600000 ;
    END
  END CNN_pk_out_3__rdb_addr__1_
  PIN CNN_pk_out_3__rdb_addr__0_
    DIRECTION OUTPUT ;
    USE SIGNAL ;
    ANTENNAPARTIALMETALAREA 0.4 LAYER M3  ;
    ANTENNAPARTIALMETALSIDEAREA 0.004 LAYER M3  ;
    ANTENNAPARTIALCUTAREA 0.08 LAYER V3  ;
    ANTENNADIFFAREA 3.52 LAYER M4  ;
    ANTENNAPARTIALMETALAREA 16.8 LAYER M4  ;
    ANTENNAPARTIALMETALSIDEAREA 0.1696 LAYER M4  ;
    PORT
      LAYER M3 ;
        RECT 47.500000 0.000000 47.700000 0.600000 ;
    END
  END CNN_pk_out_3__rdb_addr__0_
  PIN CNN_pk_out_2__PE_state__2_
    DIRECTION OUTPUT ;
    USE SIGNAL ;
    ANTENNAPARTIALMETALAREA 0.14 LAYER M3  ;
    ANTENNAPARTIALMETALSIDEAREA 0.0014 LAYER M3  ;
    ANTENNAPARTIALCUTAREA 0.08 LAYER V3  ;
    ANTENNADIFFAREA 3.52 LAYER M4  ;
    ANTENNAPARTIALMETALAREA 30.28 LAYER M4  ;
    ANTENNAPARTIALMETALSIDEAREA 0.3048 LAYER M4  ;
    PORT
      LAYER M3 ;
        RECT 95.500000 0.000000 95.700000 0.600000 ;
    END
  END CNN_pk_out_2__PE_state__2_
  PIN CNN_pk_out_2__PE_state__1_
    DIRECTION OUTPUT ;
    USE SIGNAL ;
    ANTENNAPARTIALMETALAREA 0.32 LAYER M3  ;
    ANTENNAPARTIALMETALSIDEAREA 0.0032 LAYER M3  ;
    ANTENNAPARTIALCUTAREA 0.08 LAYER V3  ;
    ANTENNADIFFAREA 3.52 LAYER M4  ;
    ANTENNAPARTIALMETALAREA 8.88 LAYER M4  ;
    ANTENNAPARTIALMETALSIDEAREA 0.0904 LAYER M4  ;
    PORT
      LAYER M3 ;
        RECT 97.500000 0.000000 97.700000 0.600000 ;
    END
  END CNN_pk_out_2__PE_state__1_
  PIN CNN_pk_out_2__PE_state__0_
    DIRECTION OUTPUT ;
    USE SIGNAL ;
    ANTENNAPARTIALMETALAREA 0.16 LAYER M3  ;
    ANTENNAPARTIALMETALSIDEAREA 0.0016 LAYER M3  ;
    ANTENNAPARTIALCUTAREA 0.08 LAYER V3  ;
    ANTENNADIFFAREA 3.52 LAYER M4  ;
    ANTENNAPARTIALMETALAREA 7.96 LAYER M4  ;
    ANTENNAPARTIALMETALSIDEAREA 0.0816 LAYER M4  ;
    PORT
      LAYER M3 ;
        RECT 99.500000 0.000000 99.700000 0.600000 ;
    END
  END CNN_pk_out_2__PE_state__0_
  PIN CNN_pk_out_2__wrb_data__7_
    DIRECTION OUTPUT ;
    USE SIGNAL ;
    ANTENNAPARTIALMETALAREA 0.08 LAYER M3  ;
    ANTENNAPARTIALMETALSIDEAREA 0.0008 LAYER M3  ;
    ANTENNAPARTIALCUTAREA 0.04 LAYER V3  ;
    ANTENNADIFFAREA 3.52 LAYER M4  ;
    ANTENNAPARTIALMETALAREA 8.24 LAYER M4  ;
    ANTENNAPARTIALMETALSIDEAREA 0.084 LAYER M4  ;
    PORT
      LAYER M3 ;
        RECT 55.500000 0.000000 55.700000 0.600000 ;
    END
  END CNN_pk_out_2__wrb_data__7_
  PIN CNN_pk_out_2__wrb_data__6_
    DIRECTION OUTPUT ;
    USE SIGNAL ;
    ANTENNAPARTIALMETALAREA 0.16 LAYER M3  ;
    ANTENNAPARTIALMETALSIDEAREA 0.0016 LAYER M3  ;
    ANTENNAPARTIALCUTAREA 0.08 LAYER V3  ;
    ANTENNADIFFAREA 3.52 LAYER M4  ;
    ANTENNAPARTIALMETALAREA 9.12 LAYER M4  ;
    ANTENNAPARTIALMETALSIDEAREA 0.0928 LAYER M4  ;
    PORT
      LAYER M3 ;
        RECT 57.500000 0.000000 57.700000 0.600000 ;
    END
  END CNN_pk_out_2__wrb_data__6_
  PIN CNN_pk_out_2__wrb_data__5_
    DIRECTION OUTPUT ;
    USE SIGNAL ;
    ANTENNAPARTIALMETALAREA 0.06 LAYER M3  ;
    ANTENNAPARTIALMETALSIDEAREA 0.0006 LAYER M3  ;
    ANTENNAPARTIALCUTAREA 0.04 LAYER V3  ;
    ANTENNADIFFAREA 3.52 LAYER M4  ;
    ANTENNAPARTIALMETALAREA 26.16 LAYER M4  ;
    ANTENNAPARTIALMETALSIDEAREA 0.2632 LAYER M4  ;
    PORT
      LAYER M3 ;
        RECT 59.500000 0.000000 59.700000 0.600000 ;
    END
  END CNN_pk_out_2__wrb_data__5_
  PIN CNN_pk_out_2__wrb_data__4_
    DIRECTION OUTPUT ;
    USE SIGNAL ;
    ANTENNAPARTIALMETALAREA 0.16 LAYER M3  ;
    ANTENNAPARTIALMETALSIDEAREA 0.0016 LAYER M3  ;
    ANTENNAPARTIALCUTAREA 0.08 LAYER V3  ;
    ANTENNADIFFAREA 3.52 LAYER M4  ;
    ANTENNAPARTIALMETALAREA 4.16 LAYER M4  ;
    ANTENNAPARTIALMETALSIDEAREA 0.0432 LAYER M4  ;
    PORT
      LAYER M3 ;
        RECT 61.500000 0.000000 61.700000 0.600000 ;
    END
  END CNN_pk_out_2__wrb_data__4_
  PIN CNN_pk_out_2__wrb_data__3_
    DIRECTION OUTPUT ;
    USE SIGNAL ;
    ANTENNAPARTIALMETALAREA 0.4 LAYER M3  ;
    ANTENNAPARTIALMETALSIDEAREA 0.004 LAYER M3  ;
    ANTENNAPARTIALCUTAREA 0.08 LAYER V3  ;
    ANTENNADIFFAREA 3.52 LAYER M4  ;
    ANTENNAPARTIALMETALAREA 23.12 LAYER M4  ;
    ANTENNAPARTIALMETALSIDEAREA 0.2328 LAYER M4  ;
    PORT
      LAYER M3 ;
        RECT 63.500000 0.000000 63.700000 0.600000 ;
    END
  END CNN_pk_out_2__wrb_data__3_
  PIN CNN_pk_out_2__wrb_data__2_
    DIRECTION OUTPUT ;
    USE SIGNAL ;
    ANTENNAPARTIALMETALAREA 1.68 LAYER M3  ;
    ANTENNAPARTIALMETALSIDEAREA 0.0168 LAYER M3  ;
    ANTENNAPARTIALCUTAREA 0.08 LAYER V3  ;
    ANTENNADIFFAREA 3.52 LAYER M4  ;
    ANTENNAPARTIALMETALAREA 15.2 LAYER M4  ;
    ANTENNAPARTIALMETALSIDEAREA 0.1536 LAYER M4  ;
    PORT
      LAYER M3 ;
        RECT 65.500000 0.000000 65.700000 0.600000 ;
    END
  END CNN_pk_out_2__wrb_data__2_
  PIN CNN_pk_out_2__wrb_data__1_
    DIRECTION OUTPUT ;
    USE SIGNAL ;
    ANTENNAPARTIALMETALAREA 0.32 LAYER M3  ;
    ANTENNAPARTIALMETALSIDEAREA 0.0032 LAYER M3  ;
    ANTENNAPARTIALCUTAREA 0.08 LAYER V3  ;
    ANTENNADIFFAREA 3.52 LAYER M4  ;
    ANTENNAPARTIALMETALAREA 23.6 LAYER M4  ;
    ANTENNAPARTIALMETALSIDEAREA 0.2376 LAYER M4  ;
    PORT
      LAYER M3 ;
        RECT 67.500000 0.000000 67.700000 0.600000 ;
    END
  END CNN_pk_out_2__wrb_data__1_
  PIN CNN_pk_out_2__wrb_data__0_
    DIRECTION OUTPUT ;
    USE SIGNAL ;
    ANTENNAPARTIALMETALAREA 0.16 LAYER M3  ;
    ANTENNAPARTIALMETALSIDEAREA 0.0016 LAYER M3  ;
    ANTENNAPARTIALCUTAREA 0.08 LAYER V3  ;
    ANTENNADIFFAREA 3.52 LAYER M4  ;
    ANTENNAPARTIALMETALAREA 20.84 LAYER M4  ;
    ANTENNAPARTIALMETALSIDEAREA 0.2112 LAYER M4  ;
    PORT
      LAYER M3 ;
        RECT 69.500000 0.000000 69.700000 0.600000 ;
    END
  END CNN_pk_out_2__wrb_data__0_
  PIN CNN_pk_out_2__wrb_addr__3_
    DIRECTION OUTPUT ;
    USE SIGNAL ;
    ANTENNAPARTIALMETALAREA 0.32 LAYER M3  ;
    ANTENNAPARTIALMETALSIDEAREA 0.0032 LAYER M3  ;
    ANTENNAPARTIALCUTAREA 0.08 LAYER V3  ;
    ANTENNADIFFAREA 3.52 LAYER M4  ;
    ANTENNAPARTIALMETALAREA 22.16 LAYER M4  ;
    ANTENNAPARTIALMETALSIDEAREA 0.2232 LAYER M4  ;
    PORT
      LAYER M3 ;
        RECT 71.500000 0.000000 71.700000 0.600000 ;
    END
  END CNN_pk_out_2__wrb_addr__3_
  PIN CNN_pk_out_2__wrb_addr__2_
    DIRECTION OUTPUT ;
    USE SIGNAL ;
    ANTENNAPARTIALMETALAREA 0.16 LAYER M3  ;
    ANTENNAPARTIALMETALSIDEAREA 0.0016 LAYER M3  ;
    ANTENNAPARTIALCUTAREA 0.08 LAYER V3  ;
    ANTENNADIFFAREA 3.52 LAYER M4  ;
    ANTENNAPARTIALMETALAREA 27.92 LAYER M4  ;
    ANTENNAPARTIALMETALSIDEAREA 0.2808 LAYER M4  ;
    PORT
      LAYER M3 ;
        RECT 73.500000 0.000000 73.700000 0.600000 ;
    END
  END CNN_pk_out_2__wrb_addr__2_
  PIN CNN_pk_out_2__wrb_addr__1_
    DIRECTION OUTPUT ;
    USE SIGNAL ;
    ANTENNAPARTIALMETALAREA 0.16 LAYER M3  ;
    ANTENNAPARTIALMETALSIDEAREA 0.0016 LAYER M3  ;
    ANTENNAPARTIALCUTAREA 0.08 LAYER V3  ;
    ANTENNADIFFAREA 3.52 LAYER M4  ;
    ANTENNAPARTIALMETALAREA 24.8 LAYER M4  ;
    ANTENNAPARTIALMETALSIDEAREA 0.2496 LAYER M4  ;
    PORT
      LAYER M3 ;
        RECT 75.500000 0.000000 75.700000 0.600000 ;
    END
  END CNN_pk_out_2__wrb_addr__1_
  PIN CNN_pk_out_2__wrb_addr__0_
    DIRECTION OUTPUT ;
    USE SIGNAL ;
    ANTENNAPARTIALMETALAREA 0.16 LAYER M3  ;
    ANTENNAPARTIALMETALSIDEAREA 0.0016 LAYER M3  ;
    ANTENNAPARTIALCUTAREA 0.08 LAYER V3  ;
    ANTENNADIFFAREA 3.52 LAYER M4  ;
    ANTENNAPARTIALMETALAREA 11.96 LAYER M4  ;
    ANTENNAPARTIALMETALSIDEAREA 0.1216 LAYER M4  ;
    PORT
      LAYER M3 ;
        RECT 77.500000 0.000000 77.700000 0.600000 ;
    END
  END CNN_pk_out_2__wrb_addr__0_
  PIN CNN_pk_out_2__wrb__3_
    DIRECTION OUTPUT ;
    USE SIGNAL ;
    ANTENNAPARTIALMETALAREA 0.16 LAYER M3  ;
    ANTENNAPARTIALMETALSIDEAREA 0.0016 LAYER M3  ;
    ANTENNAPARTIALCUTAREA 0.08 LAYER V3  ;
    ANTENNADIFFAREA 2.172 LAYER M4  ;
    ANTENNAPARTIALMETALAREA 1.48 LAYER M4  ;
    ANTENNAPARTIALMETALSIDEAREA 0.0152 LAYER M4  ;
    PORT
      LAYER M3 ;
        RECT 79.500000 0.000000 79.700000 0.600000 ;
    END
  END CNN_pk_out_2__wrb__3_
  PIN CNN_pk_out_2__wrb__2_
    DIRECTION OUTPUT ;
    USE SIGNAL ;
    ANTENNAPARTIALMETALAREA 0.08 LAYER M3  ;
    ANTENNAPARTIALMETALSIDEAREA 0.0008 LAYER M3  ;
    ANTENNAPARTIALCUTAREA 0.04 LAYER V3  ;
    ANTENNADIFFAREA 2.172 LAYER M4  ;
    ANTENNAPARTIALMETALAREA 1.4 LAYER M4  ;
    ANTENNAPARTIALMETALSIDEAREA 0.0144 LAYER M4  ;
    PORT
      LAYER M3 ;
        RECT 81.500000 0.000000 81.700000 0.600000 ;
    END
  END CNN_pk_out_2__wrb__2_
  PIN CNN_pk_out_2__wrb__1_
    DIRECTION OUTPUT ;
    USE SIGNAL ;
    ANTENNAPARTIALMETALAREA 0.64 LAYER M3  ;
    ANTENNAPARTIALMETALSIDEAREA 0.0064 LAYER M3  ;
    ANTENNAPARTIALCUTAREA 0.08 LAYER V3  ;
    ANTENNADIFFAREA 3.196 LAYER M4  ;
    ANTENNAPARTIALMETALAREA 2.56 LAYER M4  ;
    ANTENNAPARTIALMETALSIDEAREA 0.0264 LAYER M4  ;
    PORT
      LAYER M3 ;
        RECT 83.500000 0.000000 83.700000 0.600000 ;
    END
  END CNN_pk_out_2__wrb__1_
  PIN CNN_pk_out_2__wrb__0_
    DIRECTION OUTPUT ;
    USE SIGNAL ;
    ANTENNAPARTIALMETALAREA 0.32 LAYER M3  ;
    ANTENNAPARTIALMETALSIDEAREA 0.0032 LAYER M3  ;
    ANTENNAPARTIALCUTAREA 0.08 LAYER V3  ;
    ANTENNADIFFAREA 3.196 LAYER M4  ;
    ANTENNAPARTIALMETALAREA 1.4 LAYER M4  ;
    ANTENNAPARTIALMETALSIDEAREA 0.0144 LAYER M4  ;
    PORT
      LAYER M3 ;
        RECT 85.500000 0.000000 85.700000 0.600000 ;
    END
  END CNN_pk_out_2__wrb__0_
  PIN CNN_pk_out_2__rdb_addr__3_
    DIRECTION OUTPUT ;
    USE SIGNAL ;
    ANTENNAPARTIALMETALAREA 0.4 LAYER M3  ;
    ANTENNAPARTIALMETALSIDEAREA 0.004 LAYER M3  ;
    ANTENNAPARTIALCUTAREA 0.08 LAYER V3  ;
    ANTENNADIFFAREA 3.52 LAYER M4  ;
    ANTENNAPARTIALMETALAREA 16 LAYER M4  ;
    ANTENNAPARTIALMETALSIDEAREA 0.1624 LAYER M4  ;
    PORT
      LAYER M3 ;
        RECT 87.500000 0.000000 87.700000 0.600000 ;
    END
  END CNN_pk_out_2__rdb_addr__3_
  PIN CNN_pk_out_2__rdb_addr__2_
    DIRECTION OUTPUT ;
    USE SIGNAL ;
    ANTENNAPARTIALMETALAREA 0.16 LAYER M3  ;
    ANTENNAPARTIALMETALSIDEAREA 0.0016 LAYER M3  ;
    ANTENNAPARTIALCUTAREA 0.08 LAYER V3  ;
    ANTENNADIFFAREA 3.52 LAYER M4  ;
    ANTENNAPARTIALMETALAREA 10 LAYER M4  ;
    ANTENNAPARTIALMETALSIDEAREA 0.1016 LAYER M4  ;
    PORT
      LAYER M3 ;
        RECT 89.500000 0.000000 89.700000 0.600000 ;
    END
  END CNN_pk_out_2__rdb_addr__2_
  PIN CNN_pk_out_2__rdb_addr__1_
    DIRECTION OUTPUT ;
    USE SIGNAL ;
    ANTENNAPARTIALMETALAREA 0.16 LAYER M3  ;
    ANTENNAPARTIALMETALSIDEAREA 0.0016 LAYER M3  ;
    ANTENNAPARTIALCUTAREA 0.08 LAYER V3  ;
    ANTENNADIFFAREA 3.52 LAYER M4  ;
    ANTENNAPARTIALMETALAREA 6.08 LAYER M4  ;
    ANTENNAPARTIALMETALSIDEAREA 0.0624 LAYER M4  ;
    PORT
      LAYER M3 ;
        RECT 91.500000 0.000000 91.700000 0.600000 ;
    END
  END CNN_pk_out_2__rdb_addr__1_
  PIN CNN_pk_out_2__rdb_addr__0_
    DIRECTION OUTPUT ;
    USE SIGNAL ;
    ANTENNAPARTIALMETALAREA 0.16 LAYER M3  ;
    ANTENNAPARTIALMETALSIDEAREA 0.0016 LAYER M3  ;
    ANTENNAPARTIALCUTAREA 0.08 LAYER V3  ;
    ANTENNADIFFAREA 3.52 LAYER M4  ;
    ANTENNAPARTIALMETALAREA 16.8 LAYER M4  ;
    ANTENNAPARTIALMETALSIDEAREA 0.1696 LAYER M4  ;
    PORT
      LAYER M3 ;
        RECT 93.500000 0.000000 93.700000 0.600000 ;
    END
  END CNN_pk_out_2__rdb_addr__0_
  PIN CNN_pk_out_1__PE_state__2_
    DIRECTION OUTPUT ;
    USE SIGNAL ;
    ANTENNAPARTIALMETALAREA 0.08 LAYER M3  ;
    ANTENNAPARTIALMETALSIDEAREA 0.0008 LAYER M3  ;
    ANTENNAPARTIALCUTAREA 0.04 LAYER V3  ;
    ANTENNADIFFAREA 3.52 LAYER M4  ;
    ANTENNAPARTIALMETALAREA 30.28 LAYER M4  ;
    ANTENNAPARTIALMETALSIDEAREA 0.3048 LAYER M4  ;
    PORT
      LAYER M3 ;
        RECT 141.500000 0.000000 141.700000 0.600000 ;
    END
  END CNN_pk_out_1__PE_state__2_
  PIN CNN_pk_out_1__PE_state__1_
    DIRECTION OUTPUT ;
    USE SIGNAL ;
    ANTENNAPARTIALMETALAREA 0.08 LAYER M3  ;
    ANTENNAPARTIALMETALSIDEAREA 0.0008 LAYER M3  ;
    ANTENNAPARTIALCUTAREA 0.04 LAYER V3  ;
    ANTENNADIFFAREA 3.52 LAYER M4  ;
    ANTENNAPARTIALMETALAREA 8.88 LAYER M4  ;
    ANTENNAPARTIALMETALSIDEAREA 0.0904 LAYER M4  ;
    PORT
      LAYER M3 ;
        RECT 143.500000 0.000000 143.700000 0.600000 ;
    END
  END CNN_pk_out_1__PE_state__1_
  PIN CNN_pk_out_1__PE_state__0_
    DIRECTION OUTPUT ;
    USE SIGNAL ;
    ANTENNAPARTIALMETALAREA 0.16 LAYER M3  ;
    ANTENNAPARTIALMETALSIDEAREA 0.0016 LAYER M3  ;
    ANTENNAPARTIALCUTAREA 0.08 LAYER V3  ;
    ANTENNADIFFAREA 3.52 LAYER M4  ;
    ANTENNAPARTIALMETALAREA 7.96 LAYER M4  ;
    ANTENNAPARTIALMETALSIDEAREA 0.0816 LAYER M4  ;
    PORT
      LAYER M3 ;
        RECT 145.500000 0.000000 145.700000 0.600000 ;
    END
  END CNN_pk_out_1__PE_state__0_
  PIN CNN_pk_out_1__wrb_data__7_
    DIRECTION OUTPUT ;
    USE SIGNAL ;
    ANTENNAPARTIALMETALAREA 0.16 LAYER M3  ;
    ANTENNAPARTIALMETALSIDEAREA 0.0016 LAYER M3  ;
    ANTENNAPARTIALCUTAREA 0.08 LAYER V3  ;
    ANTENNADIFFAREA 3.52 LAYER M4  ;
    ANTENNAPARTIALMETALAREA 8.24 LAYER M4  ;
    ANTENNAPARTIALMETALSIDEAREA 0.084 LAYER M4  ;
    PORT
      LAYER M3 ;
        RECT 101.500000 0.000000 101.700000 0.600000 ;
    END
  END CNN_pk_out_1__wrb_data__7_
  PIN CNN_pk_out_1__wrb_data__6_
    DIRECTION OUTPUT ;
    USE SIGNAL ;
    ANTENNAPARTIALMETALAREA 0.4 LAYER M3  ;
    ANTENNAPARTIALMETALSIDEAREA 0.004 LAYER M3  ;
    ANTENNAPARTIALCUTAREA 0.08 LAYER V3  ;
    ANTENNADIFFAREA 3.52 LAYER M4  ;
    ANTENNAPARTIALMETALAREA 9.12 LAYER M4  ;
    ANTENNAPARTIALMETALSIDEAREA 0.0928 LAYER M4  ;
    PORT
      LAYER M3 ;
        RECT 103.500000 0.000000 103.700000 0.600000 ;
    END
  END CNN_pk_out_1__wrb_data__6_
  PIN CNN_pk_out_1__wrb_data__5_
    DIRECTION OUTPUT ;
    USE SIGNAL ;
    ANTENNAPARTIALMETALAREA 0.16 LAYER M3  ;
    ANTENNAPARTIALMETALSIDEAREA 0.0016 LAYER M3  ;
    ANTENNAPARTIALCUTAREA 0.08 LAYER V3  ;
    ANTENNADIFFAREA 3.52 LAYER M4  ;
    ANTENNAPARTIALMETALAREA 26.16 LAYER M4  ;
    ANTENNAPARTIALMETALSIDEAREA 0.2632 LAYER M4  ;
    PORT
      LAYER M3 ;
        RECT 105.500000 0.000000 105.700000 0.600000 ;
    END
  END CNN_pk_out_1__wrb_data__5_
  PIN CNN_pk_out_1__wrb_data__4_
    DIRECTION OUTPUT ;
    USE SIGNAL ;
    ANTENNAPARTIALCUTAREA 0.04 LAYER V3  ;
    ANTENNADIFFAREA 3.52 LAYER M4  ;
    ANTENNAPARTIALMETALAREA 4.16 LAYER M4  ;
    ANTENNAPARTIALMETALSIDEAREA 0.0432 LAYER M4  ;
    PORT
      LAYER M3 ;
        RECT 107.500000 0.000000 107.700000 0.600000 ;
    END
  END CNN_pk_out_1__wrb_data__4_
  PIN CNN_pk_out_1__wrb_data__3_
    DIRECTION OUTPUT ;
    USE SIGNAL ;
    ANTENNAPARTIALMETALAREA 0.16 LAYER M3  ;
    ANTENNAPARTIALMETALSIDEAREA 0.0016 LAYER M3  ;
    ANTENNAPARTIALCUTAREA 0.08 LAYER V3  ;
    ANTENNADIFFAREA 3.52 LAYER M4  ;
    ANTENNAPARTIALMETALAREA 23.12 LAYER M4  ;
    ANTENNAPARTIALMETALSIDEAREA 0.2328 LAYER M4  ;
    PORT
      LAYER M3 ;
        RECT 109.500000 0.000000 109.700000 0.600000 ;
    END
  END CNN_pk_out_1__wrb_data__3_
  PIN CNN_pk_out_1__wrb_data__2_
    DIRECTION OUTPUT ;
    USE SIGNAL ;
    ANTENNAPARTIALMETALAREA 0.16 LAYER M3  ;
    ANTENNAPARTIALMETALSIDEAREA 0.0016 LAYER M3  ;
    ANTENNAPARTIALCUTAREA 0.08 LAYER V3  ;
    ANTENNADIFFAREA 3.52 LAYER M4  ;
    ANTENNAPARTIALMETALAREA 15.2 LAYER M4  ;
    ANTENNAPARTIALMETALSIDEAREA 0.1536 LAYER M4  ;
    PORT
      LAYER M3 ;
        RECT 111.500000 0.000000 111.700000 0.600000 ;
    END
  END CNN_pk_out_1__wrb_data__2_
  PIN CNN_pk_out_1__wrb_data__1_
    DIRECTION OUTPUT ;
    USE SIGNAL ;
    ANTENNAPARTIALMETALAREA 0.16 LAYER M3  ;
    ANTENNAPARTIALMETALSIDEAREA 0.0016 LAYER M3  ;
    ANTENNAPARTIALCUTAREA 0.08 LAYER V3  ;
    ANTENNADIFFAREA 3.52 LAYER M4  ;
    ANTENNAPARTIALMETALAREA 23.6 LAYER M4  ;
    ANTENNAPARTIALMETALSIDEAREA 0.2376 LAYER M4  ;
    PORT
      LAYER M3 ;
        RECT 113.500000 0.000000 113.700000 0.600000 ;
    END
  END CNN_pk_out_1__wrb_data__1_
  PIN CNN_pk_out_1__wrb_data__0_
    DIRECTION OUTPUT ;
    USE SIGNAL ;
    ANTENNAPARTIALMETALAREA 0.16 LAYER M3  ;
    ANTENNAPARTIALMETALSIDEAREA 0.0016 LAYER M3  ;
    ANTENNAPARTIALCUTAREA 0.08 LAYER V3  ;
    ANTENNADIFFAREA 3.52 LAYER M4  ;
    ANTENNAPARTIALMETALAREA 20.84 LAYER M4  ;
    ANTENNAPARTIALMETALSIDEAREA 0.2112 LAYER M4  ;
    PORT
      LAYER M3 ;
        RECT 115.500000 0.000000 115.700000 0.600000 ;
    END
  END CNN_pk_out_1__wrb_data__0_
  PIN CNN_pk_out_1__wrb_addr__3_
    DIRECTION OUTPUT ;
    USE SIGNAL ;
    ANTENNAPARTIALMETALAREA 0.16 LAYER M3  ;
    ANTENNAPARTIALMETALSIDEAREA 0.0016 LAYER M3  ;
    ANTENNAPARTIALCUTAREA 0.08 LAYER V3  ;
    ANTENNADIFFAREA 3.52 LAYER M4  ;
    ANTENNAPARTIALMETALAREA 22.16 LAYER M4  ;
    ANTENNAPARTIALMETALSIDEAREA 0.2232 LAYER M4  ;
    PORT
      LAYER M3 ;
        RECT 117.500000 0.000000 117.700000 0.600000 ;
    END
  END CNN_pk_out_1__wrb_addr__3_
  PIN CNN_pk_out_1__wrb_addr__2_
    DIRECTION OUTPUT ;
    USE SIGNAL ;
    ANTENNAPARTIALMETALAREA 0.08 LAYER M3  ;
    ANTENNAPARTIALMETALSIDEAREA 0.0008 LAYER M3  ;
    ANTENNAPARTIALCUTAREA 0.04 LAYER V3  ;
    ANTENNADIFFAREA 3.52 LAYER M4  ;
    ANTENNAPARTIALMETALAREA 27.92 LAYER M4  ;
    ANTENNAPARTIALMETALSIDEAREA 0.2808 LAYER M4  ;
    PORT
      LAYER M3 ;
        RECT 119.500000 0.000000 119.700000 0.600000 ;
    END
  END CNN_pk_out_1__wrb_addr__2_
  PIN CNN_pk_out_1__wrb_addr__1_
    DIRECTION OUTPUT ;
    USE SIGNAL ;
    ANTENNAPARTIALMETALAREA 0.16 LAYER M3  ;
    ANTENNAPARTIALMETALSIDEAREA 0.0016 LAYER M3  ;
    ANTENNAPARTIALCUTAREA 0.08 LAYER V3  ;
    ANTENNADIFFAREA 3.52 LAYER M4  ;
    ANTENNAPARTIALMETALAREA 24.8 LAYER M4  ;
    ANTENNAPARTIALMETALSIDEAREA 0.2496 LAYER M4  ;
    PORT
      LAYER M3 ;
        RECT 121.500000 0.000000 121.700000 0.600000 ;
    END
  END CNN_pk_out_1__wrb_addr__1_
  PIN CNN_pk_out_1__wrb_addr__0_
    DIRECTION OUTPUT ;
    USE SIGNAL ;
    ANTENNAPARTIALMETALAREA 0.4 LAYER M3  ;
    ANTENNAPARTIALMETALSIDEAREA 0.004 LAYER M3  ;
    ANTENNAPARTIALCUTAREA 0.08 LAYER V3  ;
    ANTENNADIFFAREA 3.52 LAYER M4  ;
    ANTENNAPARTIALMETALAREA 11.96 LAYER M4  ;
    ANTENNAPARTIALMETALSIDEAREA 0.1216 LAYER M4  ;
    PORT
      LAYER M3 ;
        RECT 123.500000 0.000000 123.700000 0.600000 ;
    END
  END CNN_pk_out_1__wrb_addr__0_
  PIN CNN_pk_out_1__wrb__3_
    DIRECTION OUTPUT ;
    USE SIGNAL ;
    ANTENNAPARTIALMETALAREA 2 LAYER M3  ;
    ANTENNAPARTIALMETALSIDEAREA 0.02 LAYER M3  ;
    ANTENNAPARTIALCUTAREA 0.08 LAYER V3  ;
    ANTENNADIFFAREA 2.172 LAYER M4  ;
    ANTENNAPARTIALMETALAREA 1.24 LAYER M4  ;
    ANTENNAPARTIALMETALSIDEAREA 0.0128 LAYER M4  ;
    PORT
      LAYER M3 ;
        RECT 125.500000 0.000000 125.700000 0.600000 ;
    END
  END CNN_pk_out_1__wrb__3_
  PIN CNN_pk_out_1__wrb__2_
    DIRECTION OUTPUT ;
    USE SIGNAL ;
    ANTENNAPARTIALMETALAREA 0.24 LAYER M3  ;
    ANTENNAPARTIALMETALSIDEAREA 0.0024 LAYER M3  ;
    ANTENNAPARTIALCUTAREA 0.08 LAYER V3  ;
    ANTENNADIFFAREA 2.172 LAYER M4  ;
    ANTENNAPARTIALMETALAREA 1.4 LAYER M4  ;
    ANTENNAPARTIALMETALSIDEAREA 0.0144 LAYER M4  ;
    PORT
      LAYER M3 ;
        RECT 127.500000 0.000000 127.700000 0.600000 ;
    END
  END CNN_pk_out_1__wrb__2_
  PIN CNN_pk_out_1__wrb__1_
    DIRECTION OUTPUT ;
    USE SIGNAL ;
    ANTENNAPARTIALMETALAREA 0.16 LAYER M3  ;
    ANTENNAPARTIALMETALSIDEAREA 0.0016 LAYER M3  ;
    ANTENNAPARTIALCUTAREA 0.08 LAYER V3  ;
    ANTENNADIFFAREA 3.196 LAYER M4  ;
    ANTENNAPARTIALMETALAREA 1.96 LAYER M4  ;
    ANTENNAPARTIALMETALSIDEAREA 0.02 LAYER M4  ;
    PORT
      LAYER M3 ;
        RECT 129.500000 0.000000 129.700000 0.600000 ;
    END
  END CNN_pk_out_1__wrb__1_
  PIN CNN_pk_out_1__wrb__0_
    DIRECTION OUTPUT ;
    USE SIGNAL ;
    ANTENNAPARTIALMETALAREA 0.08 LAYER M3  ;
    ANTENNAPARTIALMETALSIDEAREA 0.0008 LAYER M3  ;
    ANTENNAPARTIALCUTAREA 0.04 LAYER V3  ;
    ANTENNADIFFAREA 3.196 LAYER M4  ;
    ANTENNAPARTIALMETALAREA 1.88 LAYER M4  ;
    ANTENNAPARTIALMETALSIDEAREA 0.0192 LAYER M4  ;
    PORT
      LAYER M3 ;
        RECT 131.500000 0.000000 131.700000 0.600000 ;
    END
  END CNN_pk_out_1__wrb__0_
  PIN CNN_pk_out_1__rdb_addr__3_
    DIRECTION OUTPUT ;
    USE SIGNAL ;
    ANTENNAPARTIALMETALAREA 0.16 LAYER M3  ;
    ANTENNAPARTIALMETALSIDEAREA 0.0016 LAYER M3  ;
    ANTENNAPARTIALCUTAREA 0.08 LAYER V3  ;
    ANTENNADIFFAREA 3.52 LAYER M4  ;
    ANTENNAPARTIALMETALAREA 16 LAYER M4  ;
    ANTENNAPARTIALMETALSIDEAREA 0.1624 LAYER M4  ;
    PORT
      LAYER M3 ;
        RECT 133.500000 0.000000 133.700000 0.600000 ;
    END
  END CNN_pk_out_1__rdb_addr__3_
  PIN CNN_pk_out_1__rdb_addr__2_
    DIRECTION OUTPUT ;
    USE SIGNAL ;
    ANTENNAPARTIALMETALAREA 0.32 LAYER M3  ;
    ANTENNAPARTIALMETALSIDEAREA 0.0032 LAYER M3  ;
    ANTENNAPARTIALCUTAREA 0.08 LAYER V3  ;
    ANTENNADIFFAREA 3.52 LAYER M4  ;
    ANTENNAPARTIALMETALAREA 10 LAYER M4  ;
    ANTENNAPARTIALMETALSIDEAREA 0.1016 LAYER M4  ;
    PORT
      LAYER M3 ;
        RECT 135.500000 0.000000 135.700000 0.600000 ;
    END
  END CNN_pk_out_1__rdb_addr__2_
  PIN CNN_pk_out_1__rdb_addr__1_
    DIRECTION OUTPUT ;
    USE SIGNAL ;
    ANTENNAPARTIALMETALAREA 0.16 LAYER M3  ;
    ANTENNAPARTIALMETALSIDEAREA 0.0016 LAYER M3  ;
    ANTENNAPARTIALCUTAREA 0.08 LAYER V3  ;
    ANTENNADIFFAREA 3.52 LAYER M4  ;
    ANTENNAPARTIALMETALAREA 6.08 LAYER M4  ;
    ANTENNAPARTIALMETALSIDEAREA 0.0624 LAYER M4  ;
    PORT
      LAYER M3 ;
        RECT 137.500000 0.000000 137.700000 0.600000 ;
    END
  END CNN_pk_out_1__rdb_addr__1_
  PIN CNN_pk_out_1__rdb_addr__0_
    DIRECTION OUTPUT ;
    USE SIGNAL ;
    ANTENNAPARTIALMETALAREA 0.16 LAYER M3  ;
    ANTENNAPARTIALMETALSIDEAREA 0.0016 LAYER M3  ;
    ANTENNAPARTIALCUTAREA 0.08 LAYER V3  ;
    ANTENNADIFFAREA 3.52 LAYER M4  ;
    ANTENNAPARTIALMETALAREA 16.8 LAYER M4  ;
    ANTENNAPARTIALMETALSIDEAREA 0.1696 LAYER M4  ;
    PORT
      LAYER M3 ;
        RECT 139.500000 0.000000 139.700000 0.600000 ;
    END
  END CNN_pk_out_1__rdb_addr__0_
  PIN CNN_pk_out_0__PE_state__2_
    DIRECTION OUTPUT ;
    USE SIGNAL ;
    ANTENNAPARTIALMETALAREA 0.4 LAYER M3  ;
    ANTENNAPARTIALMETALSIDEAREA 0.004 LAYER M3  ;
    ANTENNAPARTIALCUTAREA 0.08 LAYER V3  ;
    ANTENNADIFFAREA 3.52 LAYER M4  ;
    ANTENNAPARTIALMETALAREA 30.28 LAYER M4  ;
    ANTENNAPARTIALMETALSIDEAREA 0.3048 LAYER M4  ;
    PORT
      LAYER M3 ;
        RECT 187.500000 0.000000 187.700000 0.600000 ;
    END
  END CNN_pk_out_0__PE_state__2_
  PIN CNN_pk_out_0__PE_state__1_
    DIRECTION OUTPUT ;
    USE SIGNAL ;
    ANTENNAPARTIALMETALAREA 0.32 LAYER M3  ;
    ANTENNAPARTIALMETALSIDEAREA 0.0032 LAYER M3  ;
    ANTENNAPARTIALCUTAREA 0.08 LAYER V3  ;
    ANTENNADIFFAREA 3.52 LAYER M4  ;
    ANTENNAPARTIALMETALAREA 8.88 LAYER M4  ;
    ANTENNAPARTIALMETALSIDEAREA 0.0904 LAYER M4  ;
    PORT
      LAYER M3 ;
        RECT 189.500000 0.000000 189.700000 0.600000 ;
    END
  END CNN_pk_out_0__PE_state__1_
  PIN CNN_pk_out_0__PE_state__0_
    DIRECTION OUTPUT ;
    USE SIGNAL ;
    ANTENNAPARTIALMETALAREA 0.16 LAYER M3  ;
    ANTENNAPARTIALMETALSIDEAREA 0.0016 LAYER M3  ;
    ANTENNAPARTIALCUTAREA 0.08 LAYER V3  ;
    ANTENNADIFFAREA 3.52 LAYER M4  ;
    ANTENNAPARTIALMETALAREA 7.96 LAYER M4  ;
    ANTENNAPARTIALMETALSIDEAREA 0.0816 LAYER M4  ;
    PORT
      LAYER M3 ;
        RECT 191.500000 0.000000 191.700000 0.600000 ;
    END
  END CNN_pk_out_0__PE_state__0_
  PIN CNN_pk_out_0__wrb_data__7_
    DIRECTION OUTPUT ;
    USE SIGNAL ;
    ANTENNAPARTIALMETALAREA 0.24 LAYER M3  ;
    ANTENNAPARTIALMETALSIDEAREA 0.0024 LAYER M3  ;
    ANTENNAPARTIALCUTAREA 0.08 LAYER V3  ;
    ANTENNADIFFAREA 3.52 LAYER M4  ;
    ANTENNAPARTIALMETALAREA 8.24 LAYER M4  ;
    ANTENNAPARTIALMETALSIDEAREA 0.084 LAYER M4  ;
    PORT
      LAYER M3 ;
        RECT 147.500000 0.000000 147.700000 0.600000 ;
    END
  END CNN_pk_out_0__wrb_data__7_
  PIN CNN_pk_out_0__wrb_data__6_
    DIRECTION OUTPUT ;
    USE SIGNAL ;
    ANTENNAPARTIALMETALAREA 0.08 LAYER M3  ;
    ANTENNAPARTIALMETALSIDEAREA 0.0008 LAYER M3  ;
    ANTENNAPARTIALCUTAREA 0.04 LAYER V3  ;
    ANTENNADIFFAREA 3.52 LAYER M4  ;
    ANTENNAPARTIALMETALAREA 9.12 LAYER M4  ;
    ANTENNAPARTIALMETALSIDEAREA 0.0928 LAYER M4  ;
    PORT
      LAYER M3 ;
        RECT 149.500000 0.000000 149.700000 0.600000 ;
    END
  END CNN_pk_out_0__wrb_data__6_
  PIN CNN_pk_out_0__wrb_data__5_
    DIRECTION OUTPUT ;
    USE SIGNAL ;
    ANTENNAPARTIALMETALAREA 0.16 LAYER M3  ;
    ANTENNAPARTIALMETALSIDEAREA 0.0016 LAYER M3  ;
    ANTENNAPARTIALCUTAREA 0.08 LAYER V3  ;
    ANTENNADIFFAREA 3.52 LAYER M4  ;
    ANTENNAPARTIALMETALAREA 26.16 LAYER M4  ;
    ANTENNAPARTIALMETALSIDEAREA 0.2632 LAYER M4  ;
    PORT
      LAYER M3 ;
        RECT 151.500000 0.000000 151.700000 0.600000 ;
    END
  END CNN_pk_out_0__wrb_data__5_
  PIN CNN_pk_out_0__wrb_data__4_
    DIRECTION OUTPUT ;
    USE SIGNAL ;
    ANTENNAPARTIALMETALAREA 0.16 LAYER M3  ;
    ANTENNAPARTIALMETALSIDEAREA 0.0016 LAYER M3  ;
    ANTENNAPARTIALCUTAREA 0.08 LAYER V3  ;
    ANTENNADIFFAREA 3.52 LAYER M4  ;
    ANTENNAPARTIALMETALAREA 4.16 LAYER M4  ;
    ANTENNAPARTIALMETALSIDEAREA 0.0432 LAYER M4  ;
    PORT
      LAYER M3 ;
        RECT 153.500000 0.000000 153.700000 0.600000 ;
    END
  END CNN_pk_out_0__wrb_data__4_
  PIN CNN_pk_out_0__wrb_data__3_
    DIRECTION OUTPUT ;
    USE SIGNAL ;
    ANTENNAPARTIALMETALAREA 0.4 LAYER M3  ;
    ANTENNAPARTIALMETALSIDEAREA 0.004 LAYER M3  ;
    ANTENNAPARTIALCUTAREA 0.08 LAYER V3  ;
    ANTENNADIFFAREA 3.52 LAYER M4  ;
    ANTENNAPARTIALMETALAREA 23.12 LAYER M4  ;
    ANTENNAPARTIALMETALSIDEAREA 0.2328 LAYER M4  ;
    PORT
      LAYER M3 ;
        RECT 155.500000 0.000000 155.700000 0.600000 ;
    END
  END CNN_pk_out_0__wrb_data__3_
  PIN CNN_pk_out_0__wrb_data__2_
    DIRECTION OUTPUT ;
    USE SIGNAL ;
    ANTENNAPARTIALMETALAREA 0.16 LAYER M3  ;
    ANTENNAPARTIALMETALSIDEAREA 0.0016 LAYER M3  ;
    ANTENNAPARTIALCUTAREA 0.08 LAYER V3  ;
    ANTENNADIFFAREA 3.52 LAYER M4  ;
    ANTENNAPARTIALMETALAREA 15.2 LAYER M4  ;
    ANTENNAPARTIALMETALSIDEAREA 0.1536 LAYER M4  ;
    PORT
      LAYER M3 ;
        RECT 157.500000 0.000000 157.700000 0.600000 ;
    END
  END CNN_pk_out_0__wrb_data__2_
  PIN CNN_pk_out_0__wrb_data__1_
    DIRECTION OUTPUT ;
    USE SIGNAL ;
    ANTENNAPARTIALMETALAREA 0.16 LAYER M3  ;
    ANTENNAPARTIALMETALSIDEAREA 0.0016 LAYER M3  ;
    ANTENNAPARTIALCUTAREA 0.08 LAYER V3  ;
    ANTENNADIFFAREA 3.52 LAYER M4  ;
    ANTENNAPARTIALMETALAREA 23.6 LAYER M4  ;
    ANTENNAPARTIALMETALSIDEAREA 0.2376 LAYER M4  ;
    PORT
      LAYER M3 ;
        RECT 159.500000 0.000000 159.700000 0.600000 ;
    END
  END CNN_pk_out_0__wrb_data__1_
  PIN CNN_pk_out_0__wrb_data__0_
    DIRECTION OUTPUT ;
    USE SIGNAL ;
    ANTENNAPARTIALMETALAREA 0.4 LAYER M3  ;
    ANTENNAPARTIALMETALSIDEAREA 0.004 LAYER M3  ;
    ANTENNAPARTIALCUTAREA 0.08 LAYER V3  ;
    ANTENNADIFFAREA 3.52 LAYER M4  ;
    ANTENNAPARTIALMETALAREA 20.84 LAYER M4  ;
    ANTENNAPARTIALMETALSIDEAREA 0.2112 LAYER M4  ;
    PORT
      LAYER M3 ;
        RECT 161.500000 0.000000 161.700000 0.600000 ;
    END
  END CNN_pk_out_0__wrb_data__0_
  PIN CNN_pk_out_0__wrb_addr__3_
    DIRECTION OUTPUT ;
    USE SIGNAL ;
    ANTENNAPARTIALMETALAREA 2 LAYER M3  ;
    ANTENNAPARTIALMETALSIDEAREA 0.02 LAYER M3  ;
    ANTENNAPARTIALCUTAREA 0.08 LAYER V3  ;
    ANTENNADIFFAREA 3.52 LAYER M4  ;
    ANTENNAPARTIALMETALAREA 22.16 LAYER M4  ;
    ANTENNAPARTIALMETALSIDEAREA 0.2232 LAYER M4  ;
    PORT
      LAYER M3 ;
        RECT 163.500000 0.000000 163.700000 0.600000 ;
    END
  END CNN_pk_out_0__wrb_addr__3_
  PIN CNN_pk_out_0__wrb_addr__2_
    DIRECTION OUTPUT ;
    USE SIGNAL ;
    ANTENNAPARTIALMETALAREA 0.32 LAYER M3  ;
    ANTENNAPARTIALMETALSIDEAREA 0.0032 LAYER M3  ;
    ANTENNAPARTIALCUTAREA 0.08 LAYER V3  ;
    ANTENNADIFFAREA 3.52 LAYER M4  ;
    ANTENNAPARTIALMETALAREA 27.92 LAYER M4  ;
    ANTENNAPARTIALMETALSIDEAREA 0.2808 LAYER M4  ;
    PORT
      LAYER M3 ;
        RECT 165.500000 0.000000 165.700000 0.600000 ;
    END
  END CNN_pk_out_0__wrb_addr__2_
  PIN CNN_pk_out_0__wrb_addr__1_
    DIRECTION OUTPUT ;
    USE SIGNAL ;
    ANTENNAPARTIALMETALAREA 0.24 LAYER M3  ;
    ANTENNAPARTIALMETALSIDEAREA 0.0024 LAYER M3  ;
    ANTENNAPARTIALCUTAREA 0.08 LAYER V3  ;
    ANTENNADIFFAREA 3.52 LAYER M4  ;
    ANTENNAPARTIALMETALAREA 24.8 LAYER M4  ;
    ANTENNAPARTIALMETALSIDEAREA 0.2496 LAYER M4  ;
    PORT
      LAYER M3 ;
        RECT 167.500000 0.000000 167.700000 0.600000 ;
    END
  END CNN_pk_out_0__wrb_addr__1_
  PIN CNN_pk_out_0__wrb_addr__0_
    DIRECTION OUTPUT ;
    USE SIGNAL ;
    ANTENNAPARTIALMETALAREA 0.16 LAYER M3  ;
    ANTENNAPARTIALMETALSIDEAREA 0.0016 LAYER M3  ;
    ANTENNAPARTIALCUTAREA 0.08 LAYER V3  ;
    ANTENNADIFFAREA 3.52 LAYER M4  ;
    ANTENNAPARTIALMETALAREA 11.96 LAYER M4  ;
    ANTENNAPARTIALMETALSIDEAREA 0.1216 LAYER M4  ;
    PORT
      LAYER M3 ;
        RECT 169.500000 0.000000 169.700000 0.600000 ;
    END
  END CNN_pk_out_0__wrb_addr__0_
  PIN CNN_pk_out_0__wrb__3_
    DIRECTION OUTPUT ;
    USE SIGNAL ;
    ANTENNAPARTIALMETALAREA 0.16 LAYER M3  ;
    ANTENNAPARTIALMETALSIDEAREA 0.0016 LAYER M3  ;
    ANTENNAPARTIALCUTAREA 0.08 LAYER V3  ;
    ANTENNADIFFAREA 2.172 LAYER M4  ;
    ANTENNAPARTIALMETALAREA 2.36 LAYER M4  ;
    ANTENNAPARTIALMETALSIDEAREA 0.024 LAYER M4  ;
    PORT
      LAYER M3 ;
        RECT 171.500000 0.000000 171.700000 0.600000 ;
    END
  END CNN_pk_out_0__wrb__3_
  PIN CNN_pk_out_0__wrb__2_
    DIRECTION OUTPUT ;
    USE SIGNAL ;
    ANTENNAPARTIALCUTAREA 0.04 LAYER V3  ;
    ANTENNADIFFAREA 2.172 LAYER M4  ;
    ANTENNAPARTIALMETALAREA 1.24 LAYER M4  ;
    ANTENNAPARTIALMETALSIDEAREA 0.0128 LAYER M4  ;
    PORT
      LAYER M3 ;
        RECT 173.500000 0.000000 173.700000 0.600000 ;
    END
  END CNN_pk_out_0__wrb__2_
  PIN CNN_pk_out_0__wrb__1_
    DIRECTION OUTPUT ;
    USE SIGNAL ;
    ANTENNAPARTIALMETALAREA 0.16 LAYER M3  ;
    ANTENNAPARTIALMETALSIDEAREA 0.0016 LAYER M3  ;
    ANTENNAPARTIALCUTAREA 0.08 LAYER V3  ;
    ANTENNADIFFAREA 3.196 LAYER M4  ;
    ANTENNAPARTIALMETALAREA 1.72 LAYER M4  ;
    ANTENNAPARTIALMETALSIDEAREA 0.0176 LAYER M4  ;
    PORT
      LAYER M3 ;
        RECT 175.500000 0.000000 175.700000 0.600000 ;
    END
  END CNN_pk_out_0__wrb__1_
  PIN CNN_pk_out_0__wrb__0_
    DIRECTION OUTPUT ;
    USE SIGNAL ;
    ANTENNAPARTIALMETALAREA 0.24 LAYER M3  ;
    ANTENNAPARTIALMETALSIDEAREA 0.0024 LAYER M3  ;
    ANTENNAPARTIALCUTAREA 0.08 LAYER V3  ;
    ANTENNADIFFAREA 3.196 LAYER M4  ;
    ANTENNAPARTIALMETALAREA 2.68 LAYER M4  ;
    ANTENNAPARTIALMETALSIDEAREA 0.028 LAYER M4  ;
    PORT
      LAYER M3 ;
        RECT 177.500000 0.000000 177.700000 0.600000 ;
    END
  END CNN_pk_out_0__wrb__0_
  PIN CNN_pk_out_0__rdb_addr__3_
    DIRECTION OUTPUT ;
    USE SIGNAL ;
    ANTENNAPARTIALMETALAREA 0.4 LAYER M3  ;
    ANTENNAPARTIALMETALSIDEAREA 0.004 LAYER M3  ;
    ANTENNAPARTIALCUTAREA 0.08 LAYER V3  ;
    ANTENNADIFFAREA 3.52 LAYER M4  ;
    ANTENNAPARTIALMETALAREA 16 LAYER M4  ;
    ANTENNAPARTIALMETALSIDEAREA 0.1624 LAYER M4  ;
    PORT
      LAYER M3 ;
        RECT 179.500000 0.000000 179.700000 0.600000 ;
    END
  END CNN_pk_out_0__rdb_addr__3_
  PIN CNN_pk_out_0__rdb_addr__2_
    DIRECTION OUTPUT ;
    USE SIGNAL ;
    ANTENNAPARTIALMETALAREA 0.4 LAYER M3  ;
    ANTENNAPARTIALMETALSIDEAREA 0.004 LAYER M3  ;
    ANTENNAPARTIALCUTAREA 0.08 LAYER V3  ;
    ANTENNADIFFAREA 3.52 LAYER M4  ;
    ANTENNAPARTIALMETALAREA 10 LAYER M4  ;
    ANTENNAPARTIALMETALSIDEAREA 0.1016 LAYER M4  ;
    PORT
      LAYER M3 ;
        RECT 181.500000 0.000000 181.700000 0.600000 ;
    END
  END CNN_pk_out_0__rdb_addr__2_
  PIN CNN_pk_out_0__rdb_addr__1_
    DIRECTION OUTPUT ;
    USE SIGNAL ;
    ANTENNAPARTIALMETALAREA 0.4 LAYER M3  ;
    ANTENNAPARTIALMETALSIDEAREA 0.004 LAYER M3  ;
    ANTENNAPARTIALCUTAREA 0.08 LAYER V3  ;
    ANTENNADIFFAREA 3.52 LAYER M4  ;
    ANTENNAPARTIALMETALAREA 6.08 LAYER M4  ;
    ANTENNAPARTIALMETALSIDEAREA 0.0624 LAYER M4  ;
    PORT
      LAYER M3 ;
        RECT 183.500000 0.000000 183.700000 0.600000 ;
    END
  END CNN_pk_out_0__rdb_addr__1_
  PIN CNN_pk_out_0__rdb_addr__0_
    DIRECTION OUTPUT ;
    USE SIGNAL ;
    ANTENNAPARTIALMETALAREA 0.4 LAYER M3  ;
    ANTENNAPARTIALMETALSIDEAREA 0.004 LAYER M3  ;
    ANTENNAPARTIALCUTAREA 0.08 LAYER V3  ;
    ANTENNADIFFAREA 3.52 LAYER M4  ;
    ANTENNAPARTIALMETALAREA 16.8 LAYER M4  ;
    ANTENNAPARTIALMETALSIDEAREA 0.1696 LAYER M4  ;
    PORT
      LAYER M3 ;
        RECT 185.500000 0.000000 185.700000 0.600000 ;
    END
  END CNN_pk_out_0__rdb_addr__0_
  PIN VSS
    DIRECTION INOUT ;
    USE GROUND ;

# P/G power stripe data as pin
    PORT
      LAYER M4 ;
        RECT 46.000000 1.000000 48.000000 78.400000 ;
        RECT 26.000000 1.000000 28.000000 78.400000 ;
        RECT 46.000000 7.000000 48.000000 73.000000 ;
        RECT 26.000000 7.000000 28.000000 73.000000 ;
        RECT 86.000000 7.000000 88.000000 73.000000 ;
        RECT 66.000000 7.000000 68.000000 73.000000 ;
        RECT 66.000000 1.000000 68.000000 78.400000 ;
        RECT 86.000000 1.000000 88.000000 78.400000 ;
        RECT 146.000000 7.000000 148.000000 73.000000 ;
        RECT 126.000000 7.000000 128.000000 73.000000 ;
        RECT 106.000000 7.000000 108.000000 73.000000 ;
        RECT 106.000000 1.000000 108.000000 78.400000 ;
        RECT 126.000000 1.000000 128.000000 78.400000 ;
        RECT 146.000000 1.000000 148.000000 78.400000 ;
        RECT 166.000000 7.000000 168.000000 73.000000 ;
        RECT 166.000000 1.000000 168.000000 78.400000 ;
        RECT 1.000000 26.000000 10.880000 28.000000 ;
        RECT 189.120000 26.000000 199.000000 28.000000 ;
        RECT 1.000000 46.000000 10.880000 48.000000 ;
        RECT 1.000000 66.000000 10.880000 68.000000 ;
        RECT 189.120000 46.000000 199.000000 48.000000 ;
        RECT 189.120000 66.000000 199.000000 68.000000 ;
    END
# end of P/G power stripe data as pin

  END VSS
  PIN VDD
    DIRECTION INOUT ;
    USE POWER ;

# P/G power stripe data as pin
    PORT
      LAYER M4 ;
        RECT 42.000000 4.000000 44.000000 75.400000 ;
        RECT 22.000000 4.000000 24.000000 75.400000 ;
        RECT 42.000000 7.000000 44.000000 73.000000 ;
        RECT 22.000000 7.000000 24.000000 73.000000 ;
        RECT 82.000000 4.000000 84.000000 75.400000 ;
        RECT 62.000000 4.000000 64.000000 75.400000 ;
        RECT 82.000000 7.000000 84.000000 73.000000 ;
        RECT 62.000000 7.000000 64.000000 73.000000 ;
        RECT 142.000000 4.000000 144.000000 75.400000 ;
        RECT 122.000000 4.000000 124.000000 75.400000 ;
        RECT 102.000000 4.000000 104.000000 75.400000 ;
        RECT 142.000000 7.000000 144.000000 73.000000 ;
        RECT 122.000000 7.000000 124.000000 73.000000 ;
        RECT 102.000000 7.000000 104.000000 73.000000 ;
        RECT 162.000000 4.000000 164.000000 75.400000 ;
        RECT 162.000000 7.000000 164.000000 73.000000 ;
    END
# end of P/G power stripe data as pin

  END VDD
  OBS
    LAYER M1 ;
      RECT 0.000000 0.000000 200.000000 80.000000 ;
    LAYER M2 ;
      RECT 0.000000 0.000000 200.000000 80.000000 ;
    LAYER M3 ;
      RECT 170.420000 77.480000 200.000000 80.000000 ;
      RECT 164.420000 77.480000 166.380000 80.000000 ;
      RECT 158.420000 77.480000 160.380000 80.000000 ;
      RECT 152.420000 77.480000 154.380000 80.000000 ;
      RECT 146.420000 77.480000 148.380000 80.000000 ;
      RECT 140.420000 77.480000 142.380000 80.000000 ;
      RECT 134.420000 77.480000 136.380000 80.000000 ;
      RECT 128.420000 77.480000 130.380000 80.000000 ;
      RECT 122.420000 77.480000 124.380000 80.000000 ;
      RECT 116.420000 77.480000 118.380000 80.000000 ;
      RECT 110.420000 77.480000 112.380000 80.000000 ;
      RECT 104.420000 77.480000 106.380000 80.000000 ;
      RECT 98.420000 77.480000 100.380000 80.000000 ;
      RECT 92.420000 77.480000 94.380000 80.000000 ;
      RECT 86.420000 77.480000 88.380000 80.000000 ;
      RECT 80.420000 77.480000 82.380000 80.000000 ;
      RECT 74.420000 77.480000 76.380000 80.000000 ;
      RECT 68.420000 77.480000 70.380000 80.000000 ;
      RECT 62.420000 77.480000 64.380000 80.000000 ;
      RECT 56.420000 77.480000 58.380000 80.000000 ;
      RECT 50.420000 77.480000 52.380000 80.000000 ;
      RECT 44.420000 77.480000 46.380000 80.000000 ;
      RECT 38.420000 77.480000 40.380000 80.000000 ;
      RECT 32.420000 77.480000 34.380000 80.000000 ;
      RECT 0.000000 77.480000 28.380000 80.000000 ;
      RECT 0.000000 2.520000 200.000000 77.480000 ;
      RECT 193.620000 0.000000 200.000000 2.520000 ;
      RECT 0.000000 0.000000 7.580000 2.520000 ;
    LAYER M4 ;
      RECT 149.920000 77.320000 164.080000 80.000000 ;
      RECT 129.920000 77.320000 144.080000 80.000000 ;
      RECT 109.920000 77.320000 124.080000 80.000000 ;
      RECT 89.920000 77.320000 104.080000 80.000000 ;
      RECT 69.920000 77.320000 84.080000 80.000000 ;
      RECT 49.920000 77.320000 64.080000 80.000000 ;
      RECT 29.920000 77.320000 44.080000 80.000000 ;
      RECT 0.000000 77.320000 24.080000 80.000000 ;
      RECT 169.920000 69.920000 200.000000 80.000000 ;
      RECT 0.000000 69.920000 20.080000 77.320000 ;
      RECT 169.920000 64.080000 187.200000 69.920000 ;
      RECT 12.800000 64.080000 20.080000 69.920000 ;
      RECT 169.920000 49.920000 200.000000 64.080000 ;
      RECT 0.000000 49.920000 20.080000 64.080000 ;
      RECT 169.920000 44.080000 187.200000 49.920000 ;
      RECT 12.800000 44.080000 20.080000 49.920000 ;
      RECT 169.920000 29.920000 200.000000 44.080000 ;
      RECT 0.000000 29.920000 20.080000 44.080000 ;
      RECT 169.920000 24.080000 187.200000 29.920000 ;
      RECT 12.800000 24.080000 20.080000 29.920000 ;
      RECT 0.000000 20.020000 20.080000 24.080000 ;
      RECT 2.520000 15.980000 20.080000 20.020000 ;
      RECT 0.000000 12.020000 20.080000 15.980000 ;
      RECT 2.520000 7.980000 20.080000 12.020000 ;
      RECT 149.920000 2.080000 160.080000 77.320000 ;
      RECT 129.920000 2.080000 140.080000 77.320000 ;
      RECT 109.920000 2.080000 120.080000 77.320000 ;
      RECT 89.920000 2.080000 100.080000 77.320000 ;
      RECT 69.920000 2.080000 80.080000 77.320000 ;
      RECT 49.920000 2.080000 60.080000 77.320000 ;
      RECT 29.920000 2.080000 40.080000 77.320000 ;
      RECT 0.000000 2.080000 20.080000 7.980000 ;
      RECT 169.920000 0.000000 200.000000 24.080000 ;
      RECT 149.920000 0.000000 164.080000 2.080000 ;
      RECT 129.920000 0.000000 144.080000 2.080000 ;
      RECT 109.920000 0.000000 124.080000 2.080000 ;
      RECT 89.920000 0.000000 104.080000 2.080000 ;
      RECT 69.920000 0.000000 84.080000 2.080000 ;
      RECT 49.920000 0.000000 64.080000 2.080000 ;
      RECT 29.920000 0.000000 44.080000 2.080000 ;
      RECT 0.000000 0.000000 24.080000 2.080000 ;
  END
END decoder

END LIBRARY
